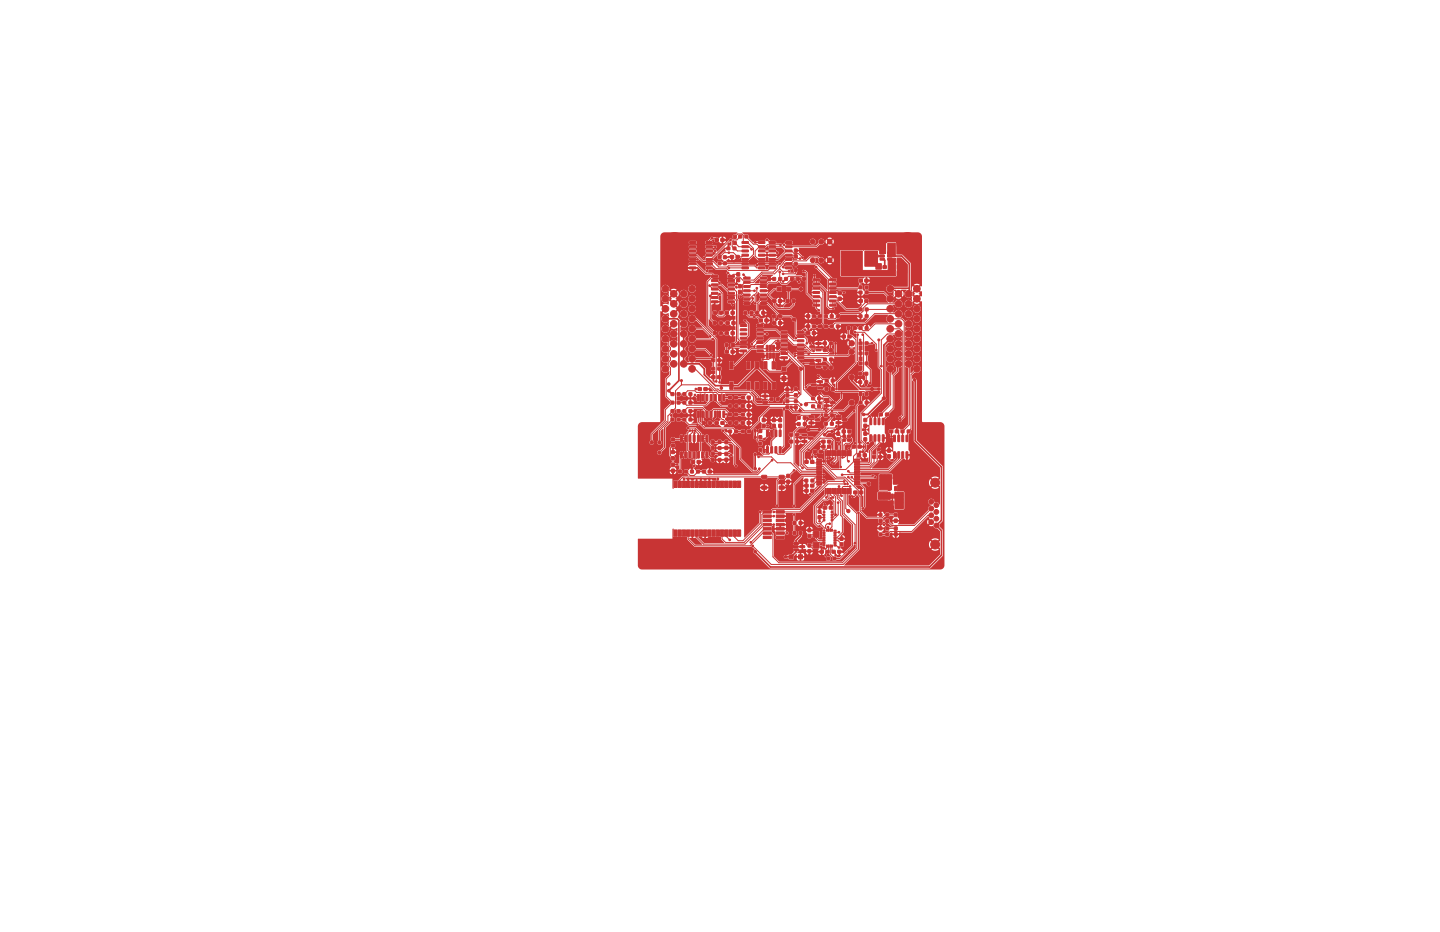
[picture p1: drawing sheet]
<svg xmlns="http://www.w3.org/2000/svg" width="432mm" height="279mm" viewBox="0 0 432 279" stroke-linecap="round" stroke-linejoin="round" font-family="sans-serif">
<g fill="#c83434" stroke="#c83434" stroke-width=".3">
<path d="M263.5 150.2h4.3v2.2h-4.3z"/>
<path d="M268.3 147.6h2.6v4.8h-2.6z"/>
<path d="M252.2 75.2h6.4v7.4h-6.4z"/>
<path d="M263.4 147.7h3.6v2h-3.6z"/>
<path d="M269.1 78h1.8v1l1 .6v2.2h-2.8z"/>
<path d="M262.5 70.9h3.1v5.1h-1.8v-1.3h-1.3z"/>
<path d="M252.3 81.1h16.3v1.5h-16.3z"/>
<path d="M267.8 143h3.6v2.1h-3.6z"/>
<path d="M266.2 72.9h2.3v4.1h-2.3z"/>
<path d="M263.8 142.3h3.5v4.6h-3.5z"/>
<path d="M259.3 75.2h3.8v1.3h1.9v.5h-1.9v2h1.2v1.7h-1.7v-.9h-3.3z"/>
<path d="M266.3 77.5h2.3v3.6h-2.3z"/>
<path d="M208.9 141h.8v.8h-.8z"/>
<path d="M207.1 141h.8v.8h-.8z"/>
<path d="M222 97.3h1.8l.1 .5-1.8 .1z"/>
<path d="M222 98.6h1.8l.1 .5h-1.8z"/>
<path d="M222 99.9l1.8-.1 .1 .5-1.8 .1z"/>
<path d="M222 101.1h1.8l.1 .5-1.8 .1z"/>
<path d="M222 102.4h1.8l.1 .5-1.8 .1z"/>
<path d="M222 103.7l1.8-.1 .1 .5-1.8 .1z"/>
<path d="M222 104.9h1.8l.1 .5-1.8 .1z"/>
<path d="M227 104.9h1.8l.1 .5-1.9 .1z"/>
<path d="M227 103.7l1.8-.1 .1 .5-1.9 .1z"/>
<path d="M227 102.4h1.8l.1 .5-1.9 .1z"/>
<path d="M227 101.1h1.8l.1 .5-1.9 .1z"/>
<path d="M227 99.9l1.8-.1 .1 .5-1.9 .1z"/>
<path d="M227 98.6h1.8l.1 .5h-1.9z"/>
<path d="M227 97.3h1.8l.1 .5-1.9 .1z"/>
<path d="M235.6 80.1l1.8-.1 .1 .5-1.8 .1z"/>
<path d="M235.6 78.8h1.8l.1 .4-1.8 .1z"/>
<path d="M235.6 77.5h1.8l.1 .5-1.8 .1z"/>
<path d="M235.6 76.2h1.8l.1 .5-1.8 .1z"/>
<path d="M235.6 75l1.8-.1 .1 .5-1.8 .1z"/>
<path d="M235.6 73.7h1.8l.1 .5-1.8 .1z"/>
<path d="M235.6 72.4h1.8l.1 .5-1.8 .1z"/>
<path d="M230.7 72.4h1.8v.5l-1.8 .1z"/>
<path d="M230.7 73.7h1.8v.5l-1.8 .1z"/>
<path d="M230.7 75l1.8-.1v.5l-1.8 .1z"/>
<path d="M230.7 76.2h1.8v.5l-1.8 .1z"/>
<path d="M230.7 77.5h1.8v.5l-1.8 .1z"/>
<path d="M230.7 78.8h1.8v.4l-1.8 .1z"/>
<path d="M230.7 80.1l1.8-.1v.5l-1.8 .1z"/>
<path d="M238.2 119.9h.8v.8h-.8z"/>
<path d="M238.2 121.7h.8v.8h-.8z"/>
<path d="M242.3 164.8h.8v.9h-.8z"/>
<path d="M242.3 163.1h.8v.9h-.8z"/>
<path d="M224.1 121.3h.9v.8h-.9z"/>
<path d="M222.3 121.3h.9v.8h-.9z"/>
<path d="M254.3 128.9h.9v.8h-.9z"/>
<path d="M252.5 128.9h1v.8h-1z"/>
<path d="M245.2 119h.9v.8h-.9z"/>
<path d="M243.4 119h.8v.8h-.8z"/>
<path d="M266.8 150.3h.9v.8h-.9z"/>
<path d="M268.5 150.3h.9v.8h-.9z"/>
<path d="M264.4 73.3h1v1.3h-1z"/>
<path d="M266.5 73.3h1v1.3h-1z"/>
<path d="M228.7 120.4l1.4-.1v.5l-1.3 .1z"/>
<path d="M228.7 118.5l1.4-.1v.5l-1.3 .1z"/>
<path d="M226.8 119.4h1.4l.1 .5-1.4 .1z"/>
<path d="M259.4 92.4h.9v.8h-.9z"/>
<path d="M257.6 92.4h.9v.8h-.9z"/>
<path d="M245.2 116.1l1.4-.1v.5l-1.3 .1z"/>
<path d="M245.2 114.2l1.4-.1v.5l-1.3 .1z"/>
<path d="M243.4 115.1h1.3l.1 .5-1.4 .1z"/>
<path d="M224.9 93.4h.8v.8h-.8z"/>
<path d="M223.1 93.4h.8v.8h-.8z"/>
<path d="M233.4 89.8h1v.8h-1z"/>
<path d="M231.7 89.8h.9v.8h-.9z"/>
<path d="M242.3 158.5h.8v.9h-.8z"/>
<path d="M242.3 160.2h.8v.9h-.8z"/>
<path d="M259.1 125.5h.8v.9h-.8z"/>
<path d="M259.1 127.2h.8v.9h-.8z"/>
<path d="M260.3 77.2h1.8v1.7h-1.8z"/>
<path d="M255.8 77.2h1.8v1.7h-1.8z"/>
<path d="M249 126.6h.9v.9h-.9z"/>
<path d="M247.2 126.6h.8v.9h-.8z"/>
<path d="M233.5 125.5h.8v.9h-.8z"/>
<path d="M233.5 127.2h.8v.9h-.8z"/>
<path d="M263.6 155.7h.8v.9h-.8z"/>
<path d="M263.6 153.9h.8v.8h-.8z"/>
<path d="M229.9 133.9l.5 .1-.1 1.8-.5-.1z"/>
<path d="M231.1 133.9l.6 .1-.1 1.8-.5-.1z"/>
<path d="M232.4 133.9l.6 .1-.1 1.8-.5-.1z"/>
<path d="M233.7 133.9l.5 .1-.1 1.8-.5-.1z"/>
<path d="M233.7 129h.5l-.1 1.9-.5-.1z"/>
<path d="M232.4 129h.6l-.1 1.9-.5-.1z"/>
<path d="M231.1 129h.6l-.1 1.9-.5-.1z"/>
<path d="M229.9 129h.5l-.1 1.9-.5-.1z"/>
<path d="M255 135.1l.2 .1v1.4h-.3z"/>
<path d="M254.5 135.1l.2 .1v1.4h-.3z"/>
<path d="M254 135.1l.2 .1v1.4h-.3z"/>
<path d="M253.5 135.1l.2 .1v1.4h-.3z"/>
<path d="M253 135.1l.2 .1v1.4h-.3z"/>
<path d="M252.5 135.1l.2 .1v1.4h-.3z"/>
<path d="M252 135.1l.2 .1v1.4h-.3z"/>
<path d="M251.5 135.1l.2 .1v1.4h-.3z"/>
<path d="M251 135.1l.2 .1v1.4h-.3z"/>
<path d="M250.5 135.1l.2 .1v1.4h-.3z"/>
<path d="M250 135.1l.2 .1v1.4h-.3z"/>
<path d="M249.5 135.1l.2 .1v1.4h-.3z"/>
<path d="M249 135.1l.2 .1v1.4h-.3z"/>
<path d="M248.5 135.1l.2 .1v1.4h-.3z"/>
<path d="M248 135.1l.2 .1v1.4h-.3z"/>
<path d="M247.5 135.1l.2 .1v1.4h-.3z"/>
<path d="M244.9 137.6h1.5v.3h-1.4z"/>
<path d="M244.9 138.1h1.5v.3h-1.4z"/>
<path d="M244.9 138.6h1.5v.3h-1.4z"/>
<path d="M244.9 139.1h1.5v.3h-1.4z"/>
<path d="M244.9 139.6h1.5v.3h-1.4z"/>
<path d="M244.9 140.1h1.5v.3h-1.4z"/>
<path d="M244.9 140.6h1.5v.3h-1.4z"/>
<path d="M244.9 141.1h1.5v.3h-1.4z"/>
<path d="M244.9 141.6h1.5v.3h-1.4z"/>
<path d="M244.9 142.1h1.5v.3h-1.4z"/>
<path d="M244.9 142.6h1.5v.3h-1.4z"/>
<path d="M244.9 143.1h1.5v.3h-1.4z"/>
<path d="M244.9 143.6h1.5v.3h-1.4z"/>
<path d="M244.9 144.1h1.5v.3h-1.4z"/>
<path d="M244.9 144.6h1.5v.3h-1.4z"/>
<path d="M244.9 145.1h1.5v.3h-1.4z"/>
<path d="M247.5 146.4l.2 .1v1.5l-.3-.1z"/>
<path d="M248 146.4l.2 .1v1.5l-.3-.1z"/>
<path d="M248.5 146.4l.2 .1v1.5l-.3-.1z"/>
<path d="M249 146.4l.2 .1v1.5l-.3-.1z"/>
<path d="M249.5 146.4l.2 .1v1.5l-.3-.1z"/>
<path d="M250 146.4l.2 .1v1.5l-.3-.1z"/>
<path d="M250.5 146.4l.2 .1v1.5l-.3-.1z"/>
<path d="M251 146.4l.2 .1v1.5l-.3-.1z"/>
<path d="M251.5 146.4l.2 .1v1.5l-.3-.1z"/>
<path d="M252 146.4l.2 .1v1.5l-.3-.1z"/>
<path d="M252.5 146.4l.2 .1v1.5l-.3-.1z"/>
<path d="M253 146.4l.2 .1v1.5l-.3-.1z"/>
<path d="M253.5 146.4l.2 .1v1.5l-.3-.1z"/>
<path d="M254 146.4l.2 .1v1.5l-.3-.1z"/>
<path d="M254.5 146.4l.2 .1v1.5l-.3-.1z"/>
<path d="M255 146.4l.2 .1v1.5l-.3-.1z"/>
<path d="M256.3 145.1h1.4l.1 .3h-1.5z"/>
<path d="M256.3 144.6h1.4l.1 .3h-1.5z"/>
<path d="M256.3 144.1h1.4l.1 .3h-1.5z"/>
<path d="M256.3 143.6h1.4l.1 .3h-1.5z"/>
<path d="M256.3 143.1h1.4l.1 .3h-1.5z"/>
<path d="M256.3 142.6h1.4l.1 .3h-1.5z"/>
<path d="M256.3 142.1h1.4l.1 .3h-1.5z"/>
<path d="M256.3 141.6h1.4l.1 .3h-1.5z"/>
<path d="M256.3 141.1h1.4l.1 .3h-1.5z"/>
<path d="M256.3 140.6h1.4l.1 .3h-1.5z"/>
<path d="M256.3 140.1h1.4l.1 .3h-1.5z"/>
<path d="M256.3 139.6h1.4l.1 .3h-1.5z"/>
<path d="M256.3 139.1h1.4l.1 .3h-1.5z"/>
<path d="M256.3 138.6h1.4l.1 .3h-1.5z"/>
<path d="M256.3 138.1h1.4l.1 .3h-1.5z"/>
<path d="M256.3 137.6h1.4l.1 .3h-1.5z"/>
<path d="M227.6 130.6h.8v.9h-.8z"/>
<path d="M227.6 128.8h.8v.8h-.8z"/>
<path d="M231.7 94.4h.8v.8h-.8z"/>
<path d="M233.5 94.4h.9v.8h-.9z"/>
<path d="M221.5 87.1h.8v.9h-.8z"/>
<path d="M221.5 85.3h.8v1h-.8z"/>
<path d="M243.4 121.4h.8v.8h-.8z"/>
<path d="M245.2 121.4h.9v.8h-.9z"/>
<path d="M247 109.9h.8v.8h-.8z"/>
<path d="M248.8 109.9h.8v.8h-.8z"/>
<path d="M215.4 135.6h.8v.9h-.8z"/>
<path d="M215.4 137.4h.8v.9h-.8z"/>
<path d="M221 81.8h.8v.9h-.8z"/>
<path d="M221 83.5h.8v.9h-.8z"/>
<path d="M238.2 118h.8v.9h-.8z"/>
<path d="M238.2 116.2h.8v.8h-.8z"/>
<path d="M265.5 123.8h.9v.9h-.9z"/>
<path d="M263.7 123.8h.9v.9h-.9z"/>
<path d="M250.8 97.4h.8v.8h-.8z"/>
<path d="M249 97.4h.8v.8h-.8z"/>
<path d="M249.2 153.3h.5v.4h-.5z"/>
<path d="M249.2 154.1h.5v.4h-.5z"/>
<path d="M249.2 154.9h.5v.4h-.5z"/>
<path d="M249.2 155.7h.5v.4h-.5z"/>
<path d="M246.9 155.7h.4v.4h-.4z"/>
<path d="M246.9 154.9h.4v.4h-.4z"/>
<path d="M246.9 154.1h.4v.4h-.4z"/>
<path d="M246.9 153.3h.4v.4h-.4z"/>
<path d="M231.6 125.5h.9v.9h-.9z"/>
<path d="M231.6 127.2h.9v.9h-.9z"/>
<path d="M214.4 71.5h1v.8h-1z"/>
<path d="M216.2 71.5h.9v.8h-.9z"/>
<path d="M256 147.2h1v.8h-1z"/>
<path d="M257.7 147.2h1v.8h-1z"/>
<path d="M242.6 124.6h1.3l.1 .5-1.4 .1z"/>
<path d="M242.6 126.5h1.3l.1 .5-1.4 .1z"/>
<path d="M244.5 125.6l1.3-.1 .1 .5-1.4 .1z"/>
<path d="M224.1 128.9h.9v.8h-.9z"/>
<path d="M222.3 128.9h.9v.8h-.9z"/>
<path d="M202 158.9h1v1.9h-1z"/>
<path d="M203.3 158.9h1v1.9h-1z"/>
<path d="M204.6 158.9h1v1.9h-1z"/>
<path d="M205.9 158.9h1v1.9h-1z"/>
<path d="M207.1 158.9h1v1.9h-1z"/>
<path d="M208.4 158.9h1v1.9h-1z"/>
<path d="M209.7 158.9h1v1.9h-1z"/>
<path d="M210.9 158.9h1v1.9h-1z"/>
<path d="M212.2 158.9h1v1.9h-1z"/>
<path d="M213.5 158.9h1v1.9h-1z"/>
<path d="M214.7 158.9h1v1.9h-1z"/>
<path d="M216 158.9h1v1.9h-1z"/>
<path d="M217.3 158.9h1v1.9h-1z"/>
<path d="M218.6 158.9h1v1.9h-1z"/>
<path d="M219.8 158.9h1v1.9h-1z"/>
<path d="M221.1 158.9h1v1.9h-1z"/>
<path d="M221.1 144.2h1v1.9h-1z"/>
<path d="M219.8 144.2h1v1.9h-1z"/>
<path d="M218.6 144.2h1v1.9h-1z"/>
<path d="M217.3 144.2h1v1.9h-1z"/>
<path d="M216 144.2h1v1.9h-1z"/>
<path d="M214.7 144.2h1v1.9h-1z"/>
<path d="M213.5 144.2h1v1.9h-1z"/>
<path d="M212.2 144.2h1v1.9h-1z"/>
<path d="M210.9 144.2h1v1.9h-1z"/>
<path d="M209.7 144.2h1v1.9h-1z"/>
<path d="M208.4 144.2h1v1.9h-1z"/>
<path d="M207.1 144.2h1v1.9h-1z"/>
<path d="M205.9 144.2h1v1.9h-1z"/>
<path d="M204.6 144.2h1v1.9h-1z"/>
<path d="M203.3 144.2h1v1.9h-1z"/>
<path d="M202 144.2h1v1.9h-1z"/>
<path d="M241.4 145.2h.9v.8h-.9z"/>
<path d="M243.1 145.2h.9v.8h-.9z"/>
<path d="M219.2 99.5h.9v.8h-.9z"/>
<path d="M217.5 99.5h.9v.8h-.9z"/>
<path d="M233.5 96.4h.9v.8h-.9z"/>
<path d="M231.7 96.4h.9v.8h-.9z"/>
<path d="M217 76.7h.8v.8h-.8z"/>
<path d="M217 78.5h.8v.9h-.8z"/>
<path d="M201.2 122.8h.9v.8h-.9z"/>
<path d="M203.1 122.8h.8v.8h-.8z"/>
<path d="M264.8 79.7h.9v.8h-.9z"/>
<path d="M263.1 79.7h.9v.8h-.9z"/>
<path d="M235.9 86.1h1.2v1.2h-1.2z"/>
<path d="M233.1 86.1h1.2v1.2h-1.2z"/>
<path d="M240.6 130.2l1.3-.1 .1 .5-1.4 .1z"/>
<path d="M240.6 132.1l1.3-.1 .1 .5-1.4 .1z"/>
<path d="M242.4 131.1h1.4l.1 .5-1.4 .1z"/>
<path d="M266.4 148.1l.5 .1-.1 1.2-.5-.1z"/>
<path d="M267.3 148.1l.6 .1-.1 1.2-.5-.1z"/>
<path d="M268.3 148.1l.5 .1-.1 1.2-.5-.1z"/>
<path d="M268.3 145.9h.5l-.1 1.2h-.5z"/>
<path d="M266.4 145.9h.5l-.1 1.2h-.5z"/>
<path d="M257.3 133.5h.9v.8h-.9z"/>
<path d="M255.6 133.5h.9v.8h-.9z"/>
<path d="M228.5 93.4h.8v.8h-.8z"/>
<path d="M226.6 93.4h.9v.8h-.9z"/>
<path d="M245.9 165h1v.8h-1z"/>
<path d="M247.7 165h.9v.8h-.9z"/>
<path d="M222.5 72.4h1.8l.1 .5-1.8 .1z"/>
<path d="M222.5 73.7h1.8l.1 .5-1.8 .1z"/>
<path d="M222.5 75l1.8-.1 .1 .5-1.8 .1z"/>
<path d="M222.5 76.2h1.8l.1 .5-1.8 .1z"/>
<path d="M222.5 77.5h1.8l.1 .5-1.8 .1z"/>
<path d="M222.5 78.8h1.8l.1 .4-1.8 .1z"/>
<path d="M222.5 80.1l1.8-.1 .1 .5-1.8 .1z"/>
<path d="M227.5 80.1l1.8-.1 .1 .5-1.9 .1z"/>
<path d="M227.5 78.8h1.8l.1 .4-1.9 .1z"/>
<path d="M227.5 77.5h1.8l.1 .5-1.9 .1z"/>
<path d="M227.5 76.2h1.8l.1 .5-1.9 .1z"/>
<path d="M227.5 75l1.8-.1 .1 .5-1.9 .1z"/>
<path d="M227.5 73.7h1.8l.1 .5-1.9 .1z"/>
<path d="M227.5 72.4h1.8l.1 .5-1.9 .1z"/>
<path d="M213.3 132.1h.8v.8h-.8z"/>
<path d="M213.3 133.9h.8v.8h-.8z"/>
<path d="M220.3 118.8h.9v.8h-.9z"/>
<path d="M218.5 118.8h.8v.8h-.8z"/>
<path d="M220.3 128.9h.9v.8h-.9z"/>
<path d="M218.5 128.9h.8v.8h-.8z"/>
<path d="M224.1 123.9h.9v.8h-.9z"/>
<path d="M222.3 123.9h.9v.8h-.9z"/>
<path d="M251.2 165h1v.8h-1z"/>
<path d="M249.5 165h.9v.8h-.9z"/>
<path d="M223.4 70.5h.8v.8h-.8z"/>
<path d="M221.6 70.5h.8v.8h-.8z"/>
<path d="M254.1 97.9h.8v.9h-.8z"/>
<path d="M255.9 97.9h.8v.9h-.8z"/>
<path d="M205.3 141h.9v.8h-.9z"/>
<path d="M203.5 141h.9v.8h-.9z"/>
<path d="M257.1 136h.9v.9h-.9z"/>
<path d="M258.8 136h1v.9h-1z"/>
<path d="M235.3 83.2h.8v.8h-.8z"/>
<path d="M237.1 83.2h.8v.8h-.8z"/>
<path d="M209.4 116.2h.9v.8h-.9z"/>
<path d="M211.1 116.2h.9v.8h-.9z"/>
<path d="M250.9 131.3h.8v.9h-.8z"/>
<path d="M250.9 129.5h.8v1h-.8z"/>
<path d="M220.3 121.3h.9v.8h-.9z"/>
<path d="M218.5 121.3h.8v.8h-.8z"/>
<path d="M239.6 159.4h.9v.8h-.9z"/>
<path d="M237.8 159.4h.8v.8h-.8z"/>
<path d="M209.2 123.3h.5l-.1 1.9-.5-.1z"/>
<path d="M210.4 123.3h.6l-.1 1.9-.5-.1z"/>
<path d="M211.7 123.3h.5v1.9l-.5-.1z"/>
<path d="M213 123.3h.5l-.1 1.9-.5-.1z"/>
<path d="M214.2 123.3h.6l-.1 1.9-.5-.1z"/>
<path d="M215.5 123.3h.6l-.1 1.9-.5-.1z"/>
<path d="M216.8 123.3h.5l-.1 1.9-.4-.1z"/>
<path d="M216.8 118.3l.5 .1-.1 1.8-.4-.1z"/>
<path d="M215.5 118.3l.6 .1-.1 1.8-.5-.1z"/>
<path d="M214.2 118.3l.6 .1-.1 1.8-.5-.1z"/>
<path d="M213 118.3l.5 .1-.1 1.8-.5-.1z"/>
<path d="M211.7 118.3l.5 .1v1.8l-.5-.1z"/>
<path d="M210.4 118.3l.6 .1-.1 1.8-.5-.1z"/>
<path d="M209.2 118.3l.5 .1-.1 1.8-.5-.1z"/>
<path d="M245.3 154.6h.8v1h-.8z"/>
<path d="M245.3 152.9h.8v.9h-.8z"/>
<path d="M243.9 162.7h1.7v1.6h-1.7z"/>
<path d="M243.9 159.4h1.7v1.6h-1.7z"/>
<path d="M217.5 103h.8v.8h-.8z"/>
<path d="M219.3 103h.8v.8h-.8z"/>
<path d="M215.8 99.5h.8v.8h-.8z"/>
<path d="M213.9 99.5h.9v.8h-.9z"/>
<path d="M266.2 77.4h1.2l.1 .5-1.3 .1z"/>
<path d="M266.2 76.5h1.2l.1 .5h-1.3z"/>
<path d="M266.2 75.5h1.2l.1 .5-1.3 .1z"/>
<path d="M263.9 75.5h1.2l.1 .5-1.2 .1z"/>
<path d="M263.9 76.5h1.2l.1 .5h-1.2z"/>
<path d="M263.9 77.4h1.2l.1 .5-1.2 .1z"/>
<path d="M233.5 83.2h.9v.8h-.9z"/>
<path d="M231.7 83.2h.8v.8h-.8z"/>
<path d="M229.8 105.9h.5v1.5l-.5-.1z"/>
<path d="M230.8 105.9h.5l-.1 1.5-.5-.1z"/>
<path d="M231.7 105.9h.5v1.5l-.5-.1z"/>
<path d="M231.7 103.6h.5v1.5l-.5-.1z"/>
<path d="M230.8 103.6h.5l-.1 1.5-.5-.1z"/>
<path d="M229.8 103.6h.5v1.5l-.5-.1z"/>
<path d="M257.5 114.2h.9v.8h-.9z"/>
<path d="M259.3 114.2h.9v.8h-.9z"/>
<path d="M245.4 94.4h.9v.8h-.9z"/>
<path d="M247.3 94.4h.8v.8h-.8z"/>
<path d="M252.8 131.6h.8v.7h-.8z"/>
<path d="M254.2 131.6h.8v.7h-.8z"/>
<path d="M254.2 130.5h.8v.7h-.8z"/>
<path d="M252.8 130.5h.8v.7h-.8z"/>
<path d="M234.2 99.4l1.8-.1 .1 .5-1.8 .1z"/>
<path d="M234.2 100.6h1.8l.1 .5-1.8 .1z"/>
<path d="M234.2 101.9h1.8l.1 .5h-1.8z"/>
<path d="M234.2 103.2l1.8-.1 .1 .5-1.8 .1z"/>
<path d="M234.2 104.4h1.8l.1 .5-1.8 .1z"/>
<path d="M234.2 105.7h1.8l.1 .5-1.8 .1z"/>
<path d="M234.2 107l1.8-.1 .1 .5-1.8 .1z"/>
<path d="M239.2 107l1.8-.1 .1 .5-1.9 .1z"/>
<path d="M239.2 105.7h1.8l.1 .5-1.9 .1z"/>
<path d="M239.2 104.4h1.8l.1 .5-1.9 .1z"/>
<path d="M239.2 103.2l1.8-.1 .1 .5-1.9 .1z"/>
<path d="M239.2 101.9h1.8l.1 .5h-1.9z"/>
<path d="M239.2 100.6h1.8l.1 .5-1.9 .1z"/>
<path d="M239.2 99.4l1.8-.1 .1 .5-1.9 .1z"/>
<path d="M215.4 78.5h.8v.9h-.8z"/>
<path d="M215.4 76.7h.8v.8h-.8z"/>
<path d="M238 162.7l1.4-.1v.5l-1.3 .1z"/>
<path d="M238 164.6l1.4-.1v.5l-1.3 .1z"/>
<path d="M239.9 163.6h1.3l.1 .5-1.4 .1z"/>
<path d="M244.7 104.6h1.4v.5l-1.3 .1z"/>
<path d="M244.7 102.7h1.4v.5l-1.3 .1z"/>
<path d="M242.8 103.7l1.4-.1 .1 .5-1.4 .1z"/>
<path d="M272 128.9h.9v.8h-.9z"/>
<path d="M270.2 128.9h.9v.8h-.9z"/>
<path d="M236.6 166.3h1.2v1.2h-1.2z"/>
<path d="M239.4 166.3h1.2v1.2h-1.2z"/>
<path d="M268 135.4l.5 .1-.1 1.8h-.5z"/>
<path d="M269.2 135.4l.6 .1-.1 1.8h-.5z"/>
<path d="M270.4 135.4l.6 .1-.1 1.8h-.5z"/>
<path d="M271.7 135.4l.5 .1v1.8h-.5z"/>
<path d="M271.7 130.5h.5v1.9l-.5-.1z"/>
<path d="M270.4 130.5h.6l-.1 1.9-.5-.1z"/>
<path d="M269.2 130.5h.6l-.1 1.9-.5-.1z"/>
<path d="M268 130.5h.5l-.1 1.9-.5-.1z"/>
<path d="M204.8 117.8h.8v.8h-.8z"/>
<path d="M206.6 117.8h.8v.8h-.8z"/>
<path d="M207.3 138.1h1v.8h-1z"/>
<path d="M209.1 138.1h.9v.8h-.9z"/>
<path d="M257.6 120.3h.9v.8h-.9z"/>
<path d="M259.4 120.3h.9v.8h-.9z"/>
<path d="M240.6 83.2h.9v.8h-.9z"/>
<path d="M238.8 83.2h.9v.8h-.9z"/>
<path d="M239.6 156.4h.9v.8h-.9z"/>
<path d="M237.8 156.4h.8v.8h-.8z"/>
<path d="M247 151.8h.9v.8h-.9z"/>
<path d="M248.7 151.8h.9v.8h-.9z"/>
<path d="M210.6 141h1v.8h-1z"/>
<path d="M212.4 141h.9v.8h-.9z"/>
<path d="M238.2 76.4h.8v.9h-.8z"/>
<path d="M238.2 74.7h.8v.9h-.8z"/>
<path d="M235.7 116.3h.8v.9h-.8z"/>
<path d="M235.7 118.1h.8v.9h-.8z"/>
<path d="M268 144.2h.9v.8h-.9z"/>
<path d="M266.3 144.2h.9v.8h-.9z"/>
<path d="M266.8 128.9h.9v.8h-.9z"/>
<path d="M268.5 128.9h.9v.8h-.9z"/>
<path d="M239.1 126.7h.8v.8h-.8z"/>
<path d="M240.9 126.7h.8v.8h-.8z"/>
<path d="M248 167h.8v.8h-.8z"/>
<path d="M249.8 167h.8v.8h-.8z"/>
<path d="M219.2 105.1h.9v.8h-.9z"/>
<path d="M217.5 105.1h.9v.8h-.9z"/>
<path d="M243.9 135h.9v.8h-.9z"/>
<path d="M245.7 135h.9v.8h-.9z"/>
<path d="M243.6 97.4h.9v.8h-.9z"/>
<path d="M241.9 97.4h.9v.8h-.9z"/>
<path d="M249.3 113.7h.8v.8h-.8z"/>
<path d="M247.5 113.7h.8v.8h-.8z"/>
<path d="M269.1 79.4h1.1v1.3h-1.1z"/>
<path d="M267.1 79.4h1v1.3h-1z"/>
<path d="M240.9 124.9h.8v.8h-.8z"/>
<path d="M239.1 124.9h.8v.8h-.8z"/>
<path d="M266.2 136.3h.8v1h-.8z"/>
<path d="M266.2 134.6h.8v.9h-.8z"/>
<path d="M217.4 135.6h.8v1h-.8z"/>
<path d="M217.4 137.3h.8v1h-.8z"/>
<path d="M248.8 107.3h.8v.8h-.8z"/>
<path d="M247 107.3h.8v.8h-.8z"/>
<path d="M201.2 120.3h.9v.8h-.9z"/>
<path d="M203.1 120.3h.8v.8h-.8z"/>
<path d="M248.2 133.5h.9v.8h-.9z"/>
<path d="M246.4 133.5h1v.8h-1z"/>
<path d="M223 83.1h1.8l.1 .5h-1.8z"/>
<path d="M223 84.4l1.8-.1 .1 .5-1.8 .1z"/>
<path d="M223 85.6h1.8l.1 .5-1.8 .1z"/>
<path d="M223 86.9h1.8l.1 .5-1.8 .1z"/>
<path d="M223 88.2h1.8l.1 .4-1.8 .1z"/>
<path d="M223 89.5l1.8-.1 .1 .5-1.8 .1z"/>
<path d="M223 90.7h1.8l.1 .5-1.8 .1z"/>
<path d="M228 90.7h1.8l.1 .5-1.9 .1z"/>
<path d="M228 89.5l1.8-.1 .1 .5-1.9 .1z"/>
<path d="M228 88.2h1.8l.1 .4-1.9 .1z"/>
<path d="M228 86.9h1.8l.1 .5-1.9 .1z"/>
<path d="M228 85.6h1.8l.1 .5-1.9 .1z"/>
<path d="M228 84.4l1.8-.1 .1 .5-1.9 .1z"/>
<path d="M228 83.1h1.8l.1 .5h-1.9z"/>
<path d="M261.7 136.5h.8v.9h-.8z"/>
<path d="M263.5 136.5h.8v.9h-.8z"/>
<path d="M244.7 109.7h1.4v.5l-1.3 .1z"/>
<path d="M244.7 107.8h1.4v.5l-1.3 .1z"/>
<path d="M242.8 108.8l1.4-.1 .1 .5-1.4 .1z"/>
<path d="M268.2 153.9h.8v.9h-.8z"/>
<path d="M268.2 155.6h.8v1h-.8z"/>
<path d="M257.6 105.5h.9v.8h-.9z"/>
<path d="M259.4 105.5h.9v.8h-.9z"/>
<path d="M213.4 110.1h.9v.8h-.9z"/>
<path d="M215.2 110.1h.9v.8h-.9z"/>
<path d="M248.2 132h.9v.8h-.9z"/>
<path d="M246.4 132h1v.8h-1z"/>
<path d="M247.2 119.5h1.3l.1 .5h-1.4z"/>
<path d="M247.2 121.4h1.3l.1 .5h-1.4z"/>
<path d="M249 120.4h1.4l.1 .5-1.4 .1z"/>
<path d="M248.8 91.2h1.8l.1 .5-1.8 .1z"/>
<path d="M248.8 90l1.8-.1 .1 .5-1.8 .1z"/>
<path d="M248.8 88.7h1.8l.1 .5h-1.8z"/>
<path d="M248.8 87.4h1.8l.1 .5-1.8 .1z"/>
<path d="M248.8 86.2l1.8-.1 .1 .5-1.8 .1z"/>
<path d="M248.8 84.9l1.8-.1 .1 .5-1.8 .1z"/>
<path d="M248.8 83.6h1.8l.1 .5-1.8 .1z"/>
<path d="M243.9 83.6h1.8l.1 .5-1.9 .1z"/>
<path d="M243.9 84.9l1.8-.1 .1 .5-1.9 .1z"/>
<path d="M243.9 86.2l1.8-.1 .1 .5-1.9 .1z"/>
<path d="M243.9 87.4h1.8l.1 .5-1.9 .1z"/>
<path d="M243.9 88.7h1.8l.1 .5h-1.9z"/>
<path d="M243.9 90l1.8-.1 .1 .5-1.9 .1z"/>
<path d="M243.9 91.2h1.8l.1 .5-1.9 .1z"/>
<path d="M228.6 127.2h.8v.9h-.8z"/>
<path d="M228.6 125.5h.8v.9h-.8z"/>
<path d="M218.8 114.5h1v2.2h-1z"/>
<path d="M223.9 114.5h1v2.2h-1z"/>
<path d="M226.4 114.5h1v2.2h-1z"/>
<path d="M229 114.5h1v2.2h-1z"/>
<path d="M231.5 114.5h1v2.2h-1z"/>
<path d="M231.5 108.4h1v2.2h-1z"/>
<path d="M229 108.4h1v2.2h-1z"/>
<path d="M226.4 108.4h1v2.2h-1z"/>
<path d="M223.9 108.4h1v2.2h-1z"/>
<path d="M218.8 108.4h1v2.2h-1z"/>
<path d="M204.8 122.8h.8v.8h-.8z"/>
<path d="M206.6 122.8h.8v.8h-.8z"/>
<path d="M216.2 126.4h.9v.8h-.9z"/>
<path d="M214.4 126.4h1v.8h-1z"/>
<path d="M259.4 85.7h.9v.9h-.9z"/>
<path d="M257.6 85.7h.9v.9h-.9z"/>
<path d="M243.2 143.7h.8v.8h-.8z"/>
<path d="M241.4 143.7h.8v.8h-.8z"/>
<path d="M265.7 158h.8v.8h-.8z"/>
<path d="M265.7 159.8h.8v.8h-.8z"/>
<path d="M215.8 93.4h.8v.8h-.8z"/>
<path d="M213.9 93.4h.9v.8h-.9z"/>
<path d="M247.5 116.2h.8v.8h-.8z"/>
<path d="M249.3 116.2h.8v.8h-.8z"/>
<path d="M257.6 94.4h.9v.8h-.9z"/>
<path d="M259.4 94.4h.9v.8h-.9z"/>
<path d="M219.5 96.4h.9v.8h-.9z"/>
<path d="M217.7 96.4h1v.8h-1z"/>
<path d="M263.6 159.8h.8v.8h-.8z"/>
<path d="M263.6 158h.8v.8h-.8z"/>
<path d="M206.8 72.4h1.8l.1 .5-1.9 .1z"/>
<path d="M206.8 73.7h1.8l.1 .5-1.9 .1z"/>
<path d="M206.8 75l1.8-.1 .1 .5-1.9 .1z"/>
<path d="M206.8 76.2h1.8l.1 .5-1.9 .1z"/>
<path d="M206.8 77.5h1.8l.1 .5-1.9 .1z"/>
<path d="M206.8 78.8h1.8l.1 .4-1.9 .1z"/>
<path d="M206.8 80.1l1.8-.1 .1 .5-1.9 .1z"/>
<path d="M211.7 80.1l1.8-.1 .1 .5-1.8 .1z"/>
<path d="M211.7 78.8h1.8l.1 .4-1.8 .1z"/>
<path d="M211.7 77.5h1.8l.1 .5-1.8 .1z"/>
<path d="M211.7 76.2h1.8l.1 .5-1.8 .1z"/>
<path d="M211.7 75l1.8-.1 .1 .5-1.8 .1z"/>
<path d="M211.7 73.7h1.8l.1 .5-1.8 .1z"/>
<path d="M211.7 72.4h1.8l.1 .5-1.8 .1z"/>
<path d="M215.4 132.1h.8v.8h-.8z"/>
<path d="M215.4 133.9h.8v.8h-.8z"/>
<path d="M220.3 123.8h.9v.8h-.9z"/>
<path d="M218.5 123.8h.8v.8h-.8z"/>
<path d="M250.7 124.6l1.4-.1v.5l-1.3 .1z"/>
<path d="M250.7 126.5l1.4-.1v.5l-1.3 .1z"/>
<path d="M252.6 125.5h1.3l.1 .5-1.4 .1z"/>
<path d="M217.4 132.1h.8v.9h-.8z"/>
<path d="M217.4 133.8h.8v.9h-.8z"/>
<path d="M227.6 95.7h1v.8h-1z"/>
<path d="M229.4 95.7h.9v.8h-.9z"/>
<path d="M249 94.4h.8v.8h-.8z"/>
<path d="M250.8 94.4h.8v.8h-.8z"/>
<path d="M238.6 132h.9v.8h-.9z"/>
<path d="M236.8 132h.8v.8h-.8z"/>
<path d="M268.2 158h.8v.9h-.8z"/>
<path d="M268.2 159.7h.8v.9h-.8z"/>
<path d="M220.7 76.6h1v.8h-1z"/>
<path d="M219 76.6h.9v.8h-.9z"/>
<path d="M201.2 125.4h.9v.8h-.9z"/>
<path d="M203.1 125.4h.8v.8h-.8z"/>
<path d="M232.8 160.7h2.4v.8h-2.4z"/>
<path d="M228.9 160.7h2.4v.8h-2.4z"/>
<path d="M232.8 159.4h2.4v.8h-2.4z"/>
<path d="M228.9 159.4h2.4v.8h-2.4z"/>
<path d="M232.8 158.2h2.4v.7h-2.4z"/>
<path d="M228.9 158.2h2.4v.7h-2.4z"/>
<path d="M232.8 156.9h2.4v.7h-2.4z"/>
<path d="M228.9 156.9h2.4v.7h-2.4z"/>
<path d="M232.8 155.6h2.4v.8h-2.4z"/>
<path d="M228.9 155.6h2.4v.8h-2.4z"/>
<path d="M232.8 154.4h2.4v.7h-2.4z"/>
<path d="M228.9 154.4h2.4v.7h-2.4z"/>
<path d="M232.8 153.1h2.4v.7h-2.4z"/>
<path d="M228.9 153.1h2.4v.7h-2.4z"/>
<path d="M259.4 117.7h.9v.8h-.9z"/>
<path d="M257.6 117.7h.9v.8h-.9z"/>
<path d="M259.4 102.5h.9v.8h-.9z"/>
<path d="M257.6 102.5h.9v.8h-.9z"/>
<path d="M243.1 138.1h.9v.8h-.9z"/>
<path d="M241.4 138.1h.9v.8h-.9z"/>
<path d="M260.9 130.4h.5l-.1 1.9-.5-.1z"/>
<path d="M262.1 130.4h.6l-.1 1.9-.5-.1z"/>
<path d="M263.3 130.4h.6l-.1 1.9-.5-.1z"/>
<path d="M264.6 130.4h.5l-.1 1.9-.4-.1z"/>
<path d="M264.6 125.4l.5 .1-.1 1.8-.4-.1z"/>
<path d="M263.3 125.4l.6 .1-.1 1.8-.5-.1z"/>
<path d="M262.1 125.4l.6 .1-.1 1.8-.5-.1z"/>
<path d="M260.9 125.4l.5 .1-.1 1.8-.5-.1z"/>
<path d="M257.5 111.6h.9v.8h-.9z"/>
<path d="M259.3 111.6h.9v.8h-.9z"/>
<path d="M241.9 99.5h.9v.8h-.9z"/>
<path d="M243.6 99.5h.9v.8h-.9z"/>
<path d="M235.9 144h.9v.9h-.9z"/>
<path d="M235.9 142.2h.9v1h-.9z"/>
<path d="M201.4 138.9h.8v1h-.8z"/>
<path d="M201.4 140.7h.8v.9h-.8z"/>
<path d="M243.1 146.7h.9v.8h-.9z"/>
<path d="M241.4 146.7h.9v.8h-.9z"/>
<path d="M201.2 117.8h.9v.8h-.9z"/>
<path d="M203.1 117.8h.8v.8h-.8z"/>
<path d="M213.3 135.6h.8v.9h-.8z"/>
<path d="M213.3 137.4h.8v.9h-.8z"/>
<path d="M231 119.3h.8v.8h-.8z"/>
<path d="M232.8 119.3h.8v.8h-.8z"/>
<path d="M204.8 125.4h.8v.8h-.8z"/>
<path d="M206.6 125.4h.8v.8h-.8z"/>
<path d="M259.3 89.8h1v.8h-1z"/>
<path d="M257.6 89.8h1v.8h-1z"/>
<path d="M204.8 120.3h.8v.8h-.8z"/>
<path d="M206.6 120.3h.8v.8h-.8z"/>
<path d="M237.6 89.8h.8v.8h-.8z"/>
<path d="M235.8 89.8h.8v.8h-.8z"/>
<path d="M251.4 87.4h.8v.9h-.8z"/>
<path d="M251.4 89.1h.8v.9h-.8z"/>
<path d="M215.8 96.4h.8v.8h-.8z"/>
<path d="M213.9 96.4h.9v.8h-.9z"/>
<path d="M213.4 82.6h1.8l.1 .5h-1.9z"/>
<path d="M213.4 83.9l1.8-.1 .1 .5-1.9 .1z"/>
<path d="M213.4 85.1h1.8l.1 .5-1.9 .1z"/>
<path d="M213.4 86.4h1.8l.1 .5-1.9 .1z"/>
<path d="M213.4 87.7l1.8-.1 .1 .5-1.9 .1z"/>
<path d="M213.4 88.9h1.8l.1 .5-1.9 .1z"/>
<path d="M213.4 90.2h1.8l.1 .5-1.9 .1z"/>
<path d="M218.3 90.2h1.8l.1 .5-1.8 .1z"/>
<path d="M218.3 88.9h1.8l.1 .5-1.8 .1z"/>
<path d="M218.3 87.7l1.8-.1 .1 .5-1.8 .1z"/>
<path d="M218.3 86.4h1.8l.1 .5-1.8 .1z"/>
<path d="M218.3 85.1h1.8l.1 .5-1.8 .1z"/>
<path d="M218.3 83.9l1.8-.1 .1 .5-1.8 .1z"/>
<path d="M218.3 82.6h1.8l.1 .5h-1.8z"/>
<path d="M204.1 135.4l.5 .1-.1 1.8h-.4z"/>
<path d="M205.4 135.4l.5 .1-.1 1.8h-.5z"/>
<path d="M206.6 135.4l.6 .1-.1 1.8h-.5z"/>
<path d="M207.9 135.4l.5 .1v1.8h-.5z"/>
<path d="M209.2 135.4l.5 .1-.1 1.8h-.5z"/>
<path d="M210.4 135.4l.6 .1-.1 1.8h-.5z"/>
<path d="M211.7 135.4l.5 .1v1.8h-.5z"/>
<path d="M211.7 130.5h.5v1.9l-.5-.1z"/>
<path d="M210.4 130.5h.6l-.1 1.9-.5-.1z"/>
<path d="M209.2 130.5h.5l-.1 1.9-.5-.1z"/>
<path d="M207.9 130.5h.5v1.9l-.5-.1z"/>
<path d="M206.6 130.5h.6l-.1 1.9-.5-.1z"/>
<path d="M205.4 130.5h.5l-.1 1.9-.5-.1z"/>
<path d="M204.1 130.5h.5l-.1 1.9-.4-.1z"/>
<path d="M257.6 83.7h1v.8h-1z"/>
<path d="M259.3 83.7h1v.8h-1z"/>
<path d="M246.7 163.4h.7v.3h-.7z"/>
<path d="M247.8 163.4h.3v.6h-.3z"/>
<path d="M248.3 163.4h.3v.6h-.3z"/>
<path d="M248.8 163.4h.3v.6h-.3z"/>
<path d="M249.3 163.4h.3v.6h-.3z"/>
<path d="M250 163.4h.7v.3h-.7z"/>
<path d="M250 162.9h.7v.3h-.7z"/>
<path d="M250 162.4h.7v.3h-.7z"/>
<path d="M250 161.9h.7v.3h-.7z"/>
<path d="M250 161.4h.7v.3h-.7z"/>
<path d="M250 160.9h.7v.3h-.7z"/>
<path d="M250 160.4h.7v.3h-.7z"/>
<path d="M250 159.9h.7v.3h-.7z"/>
<path d="M250 159.4h.7v.3h-.7z"/>
<path d="M250 158.9h.7v.3h-.7z"/>
<path d="M249.3 158.6h.3v.7h-.3z"/>
<path d="M248.8 158.6h.3v.7h-.3z"/>
<path d="M248.3 158.6h.3v.7h-.3z"/>
<path d="M247.8 158.6h.3v.7h-.3z"/>
<path d="M246.7 158.9h.7v.3h-.7z"/>
<path d="M246.7 159.4h.7v.3h-.7z"/>
<path d="M246.7 159.9h.7v.3h-.7z"/>
<path d="M246.7 160.4h.7v.3h-.7z"/>
<path d="M246.7 160.9h.7v.3h-.7z"/>
<path d="M246.7 161.4h.7v.3h-.7z"/>
<path d="M246.7 161.9h.7v.3h-.7z"/>
<path d="M246.7 162.4h.7v.3h-.7z"/>
<path d="M246.7 162.9h.7v.3h-.7z"/>
<path d="M201.4 131.3h.8v.8h-.8z"/>
<path d="M201.4 133.1h.8v.9h-.8z"/>
<path d="M265.7 153.9h.8v.8h-.8z"/>
<path d="M265.7 155.7h.8v.9h-.8z"/>
<path d="M235.7 121.7h.8v.8h-.8z"/>
<path d="M235.7 119.9h.8v.8h-.8z"/>
<path d="M234.5 110.1h1.2v1.2h-1.2z"/>
<path d="M234.5 112.9h1.2v1.2h-1.2z"/>
<path d="M238.6 129.9h.9v.9h-.9z"/>
<path d="M236.8 129.9h.8v.9h-.8z"/>
<path d="M259.1 131.3h.8v.9h-.8z"/>
<path d="M259.1 129.5h.8v1h-.8z"/>
<path d="M219.2 93.4h.9v.8h-.9z"/>
<path d="M217.5 93.4h.9v.8h-.9z"/>
<path d="M201.4 135.1h.8v.9h-.8z"/>
<path d="M201.4 136.9h.8v.9h-.8z"/>
<path d="M224.1 118.8h.9v.8h-.9z"/>
<path d="M222.3 118.8h.9v.8h-.9z"/>
<path d="M227.6 134.4h.8v.8h-.8z"/>
<path d="M227.6 132.6h.8v.8h-.8z"/>
<path d="M251.9 161h.9v1h-.9z"/>
<path d="M251.9 162.7h.9v1h-.9z"/>
<path d="M220.3 126.4h.9v.8h-.9z"/>
<path d="M218.5 126.4h.8v.8h-.8z"/>
<path d="M243.6 94.4h.9v.8h-.9z"/>
<path d="M241.9 94.4h.9v.8h-.9z"/>
<path d="M249 124.1h.9v.8h-.9z"/>
<path d="M247.2 124.1h.8v.8h-.8z"/>
<path d="M213.4 107.6h.9v.8h-.9z"/>
<path d="M215.2 107.6h.9v.8h-.9z"/>
<path d="M247 104.5h.8v.9h-.8z"/>
<path d="M248.8 104.5h.8v.9h-.8z"/>
<path d="M257.6 87.3h.9v.8h-.9z"/>
<path d="M259.4 87.3h.9v.8h-.9z"/>
<path d="M247 102.5h.8v.8h-.8z"/>
<path d="M248.8 102.5h.8v.8h-.8z"/>
<path d="M218 74.1h.8v.8h-.8z"/>
<path d="M219.8 74.1h.9v.8h-.9z"/>
<path d="M257.6 97.9h.9v.9h-.9z"/>
<path d="M259.4 97.9h.9v.9h-.9z"/>
<path d="M219.9 72.4h.8v.9h-.8z"/>
<path d="M219.9 70.6h.8v.8h-.8z"/>
<path d="M247.3 97.4h.8v.8h-.8z"/>
<path d="M245.4 97.4h.9v.8h-.9z"/>
<path d="M233.7 145.7h1.3l.2 .8-1.4 .2z"/>
<path d="M228.4 145.7h1.4l.1 .8-1.4 .2z"/>
<path d="M233.7 142.5h1.3l.2 .8-1.4 .2z"/>
<path d="M228.4 142.5h1.4l.1 .8-1.4 .2z"/>
<path d="M212.5 126.4h.8v.8h-.8z"/>
<path d="M210.6 126.4h.9v.8h-.9z"/>
<path d="M224.1 126.4h.9v.8h-.9z"/>
<path d="M222.3 126.4h.9v.8h-.9z"/>
<path d="M238.2 78.7h.8v.9h-.8z"/>
<path d="M238.2 80.6h.8v.8h-.8z"/>
<path d="M215.1 112.7h1v.8h-1z"/>
<path d="M213.4 112.7h1v.8h-1z"/>
<path d="M257.6 108.5h.9v.9h-.9z"/>
<path d="M259.4 108.5h.9v.9h-.9z"/>
<path d="M254.3 100.5h.9v.8h-.9z"/>
<path d="M252.5 100.5h1v.8h-1z"/>
<circle cx="255.4" cy="102.9" r=".8"/>
<circle cx="255.4" cy="105.5" r=".8"/>
<circle cx="255.4" cy="113.1" r=".8"/>
<circle cx="255.4" cy="120.7" r=".8"/>
<circle cx="260.5" cy="145.1" r=".5"/>
<circle cx="240.2" cy="86.7" r=".5"/>
<circle cx="202.3" cy="72.9" r="3.2"/>
<circle cx="254.4" cy="153.2" r=".5"/>
<circle cx="278.5" cy="130.1" r="3.2"/>
<circle cx="196" cy="165.7" r="3.2"/>
<circle cx="263.5" cy="134.7" r=".5"/>
<circle cx="207.5" cy="86.6" r="1"/>
<circle cx="207.5" cy="89.6" r="1"/>
<circle cx="207.5" cy="92.6" r="1"/>
<circle cx="207.5" cy="95.6" r="1"/>
<circle cx="207.5" cy="98.6" r="1"/>
<circle cx="207.5" cy="101.6" r="1"/>
<circle cx="207.5" cy="104.6" r="1"/>
<circle cx="207.5" cy="107.6" r="1"/>
<circle cx="207.5" cy="110.6" r="1"/>
<circle cx="205" cy="88.1" r="1"/>
<circle cx="205" cy="91.1" r="1"/>
<circle cx="205" cy="94.1" r="1"/>
<circle cx="205" cy="97.1" r="1"/>
<circle cx="205" cy="100.1" r="1"/>
<circle cx="205" cy="103.1" r="1"/>
<circle cx="205" cy="106.1" r="1"/>
<circle cx="205" cy="109.1" r="1"/>
<circle cx="202" cy="88.1" r="1"/>
<circle cx="202" cy="91.1" r="1"/>
<circle cx="202" cy="94.1" r="1"/>
<circle cx="202" cy="97.1" r="1"/>
<circle cx="202" cy="100.1" r="1"/>
<circle cx="202" cy="103.1" r="1"/>
<circle cx="202" cy="106.1" r="1"/>
<circle cx="202" cy="109.1" r="1"/>
<circle cx="199.5" cy="86.6" r="1"/>
<circle cx="199.5" cy="89.6" r="1"/>
<circle cx="199.5" cy="92.6" r="1"/>
<circle cx="199.5" cy="95.6" r="1"/>
<circle cx="199.5" cy="98.6" r="1"/>
<circle cx="199.5" cy="101.6" r="1"/>
<circle cx="199.5" cy="104.6" r="1"/>
<circle cx="199.5" cy="107.6" r="1"/>
<circle cx="199.5" cy="110.6" r="1"/>
<circle cx="243.7" cy="78" r=".72"/>
<circle cx="246.3" cy="78" r=".72"/>
<circle cx="248.8" cy="78" r=".72"/>
<circle cx="261.5" cy="116.6" r=".5"/>
<circle cx="195.5" cy="132.6" r=".5"/>
<circle cx="241.7" cy="121.2" r=".5"/>
<circle cx="240.2" cy="110.5" r=".5"/>
<circle cx="265" cy="119.4" r=".5"/>
<circle cx="266.9" cy="110.6" r="1"/>
<circle cx="266.9" cy="107.6" r="1"/>
<circle cx="266.9" cy="104.6" r="1"/>
<circle cx="266.9" cy="101.6" r="1"/>
<circle cx="266.9" cy="98.6" r="1"/>
<circle cx="266.9" cy="95.6" r="1"/>
<circle cx="266.9" cy="92.6" r="1"/>
<circle cx="266.9" cy="89.6" r="1"/>
<circle cx="266.9" cy="86.6" r="1"/>
<circle cx="269.4" cy="109.1" r="1"/>
<circle cx="269.4" cy="106.1" r="1"/>
<circle cx="269.4" cy="103.1" r="1"/>
<circle cx="269.4" cy="100.1" r="1"/>
<circle cx="269.4" cy="97.1" r="1"/>
<circle cx="269.4" cy="94.1" r="1"/>
<circle cx="269.4" cy="91.1" r="1"/>
<circle cx="269.4" cy="88.1" r="1"/>
<circle cx="272.4" cy="109.1" r="1"/>
<circle cx="272.4" cy="106.1" r="1"/>
<circle cx="272.4" cy="103.1" r="1"/>
<circle cx="272.4" cy="100.1" r="1"/>
<circle cx="272.4" cy="97.1" r="1"/>
<circle cx="272.4" cy="94.1" r="1"/>
<circle cx="272.4" cy="91.1" r="1"/>
<circle cx="272.4" cy="88.1" r="1"/>
<circle cx="274.9" cy="110.6" r="1"/>
<circle cx="274.9" cy="107.6" r="1"/>
<circle cx="274.9" cy="104.6" r="1"/>
<circle cx="274.9" cy="101.6" r="1"/>
<circle cx="274.9" cy="98.6" r="1"/>
<circle cx="274.9" cy="95.6" r="1"/>
<circle cx="274.9" cy="92.6" r="1"/>
<circle cx="274.9" cy="89.6" r="1"/>
<circle cx="274.9" cy="86.6" r="1"/>
<circle cx="272.2" cy="72.9" r="3.2"/>
<circle cx="197.7" cy="132.6" r=".5"/>
<circle cx="243.7" cy="72.4" r=".72"/>
<circle cx="246.3" cy="72.4" r=".72"/>
<circle cx="248.8" cy="72.4" r=".72"/>
<circle cx="238.1" cy="95.8" r=".5"/>
<circle cx="280.8" cy="151.4" r=".72"/>
<circle cx="279.2" cy="150.4" r=".72"/>
<circle cx="279.2" cy="152.4" r=".72"/>
<circle cx="279.2" cy="154.5" r=".72"/>
<circle cx="280.8" cy="153.5" r=".72"/>
<circle cx="280.8" cy="155.5" r=".72"/>
<circle cx="280.8" cy="157.5" r=".72"/>
<circle cx="279.2" cy="156.5" r=".72"/>
<circle cx="280.4" cy="163.2" r="1.35"/>
<circle cx="280.4" cy="144.7" r="1.35"/>
<circle cx="197.7" cy="135.7" r=".5"/>
<circle cx="232" cy="158.5" r=".25"/>
<circle cx="264.8" cy="135.4" r=".25"/>
<circle cx="229.2" cy="135.4" r=".25"/>
<circle cx="219.1" cy="134.2" r=".25"/>
<circle cx="257.9" cy="88.9" r=".25"/>
<circle cx="218.6" cy="73.3" r=".25"/>
<circle cx="233.8" cy="88.9" r=".25"/>
<circle cx="220.1" cy="78.3" r=".25"/>
<circle cx="263" cy="74.5" r=".38"/>
<circle cx="214.2" cy="141.5" r=".25"/>
<circle cx="253.6" cy="161.6" r=".25"/>
<circle cx="251.6" cy="100.6" r=".25"/>
<circle cx="214.5" cy="77.8" r=".25"/>
<circle cx="264" cy="72.4" r=".38"/>
<circle cx="263" cy="71.4" r=".38"/>
<circle cx="217.8" cy="129.1" r=".25"/>
<circle cx="243.2" cy="98.9" r=".25"/>
<circle cx="263" cy="73.5" r=".38"/>
<circle cx="261" cy="84.1" r=".25"/>
<circle cx="207.4" cy="140.3" r=".25"/>
<circle cx="240.7" cy="145.6" r=".25"/>
<circle cx="217.8" cy="125.5" r=".25"/>
<circle cx="251.6" cy="128.3" r=".25"/>
<circle cx="229.2" cy="94.8" r=".25"/>
<circle cx="264.8" cy="151.9" r=".38"/>
<circle cx="264" cy="71.4" r=".38"/>
<circle cx="224.4" cy="125.5" r=".25"/>
<circle cx="252.3" cy="97.8" r=".25"/>
<circle cx="270.6" cy="81.6" r=".38"/>
<circle cx="271.4" cy="79.8" r=".38"/>
<circle cx="224.4" cy="120.4" r=".25"/>
<circle cx="265" cy="71.4" r=".38"/>
<circle cx="269.4" cy="128.1" r=".25"/>
<circle cx="265.8" cy="151.9" r=".38"/>
<circle cx="247" cy="144.6" r=".25"/>
<circle cx="254.1" cy="133.7" r=".25"/>
<circle cx="245.7" cy="152.2" r=".25"/>
<circle cx="269.9" cy="156.3" r=".25"/>
<circle cx="269.6" cy="81.6" r=".38"/>
<circle cx="265" cy="72.4" r=".38"/>
<circle cx="259.1" cy="119.4" r=".3"/>
<circle cx="242.9" cy="87.7" r=".3"/>
<circle cx="265" cy="133.1" r=".25"/>
<circle cx="257.9" cy="113.3" r=".25"/>
<circle cx="208.2" cy="133.1" r=".25"/>
<circle cx="214" cy="91.5" r=".25"/>
<circle cx="231" cy="83.6" r=".25"/>
<circle cx="227.5" cy="146.1" r=".25"/>
<circle cx="270.9" cy="144.6" r=".38"/>
<circle cx="213" cy="111.8" r=".25"/>
<circle cx="246" cy="109" r=".25"/>
<circle cx="219.1" cy="137.7" r=".25"/>
<circle cx="271.4" cy="80.8" r=".38"/>
<circle cx="206.4" cy="143.6" r=".25"/>
<circle cx="216.8" cy="108.5" r=".25"/>
<circle cx="270.6" cy="78.5" r=".38"/>
<circle cx="235.1" cy="114.9" r=".25"/>
<circle cx="246.3" cy="161.3" r=".25"/>
<circle cx="273.2" cy="136.7" r=".25"/>
<circle cx="245.7" cy="120.7" r=".25"/>
<circle cx="207.1" cy="124.5" r=".25"/>
<circle cx="257.9" cy="96.1" r=".25"/>
<circle cx="260" cy="97.3" r=".25"/>
<circle cx="254.6" cy="165.4" r=".25"/>
<circle cx="247" cy="164.4" r=".25"/>
<circle cx="242.7" cy="166.4" r=".25"/>
<circle cx="231" cy="118.4" r=".25"/>
<circle cx="207.6" cy="161.6" r=".25"/>
<circle cx="249.3" cy="151.2" r=".25"/>
<circle cx="269.6" cy="78.5" r=".38"/>
<circle cx="206.1" cy="80.3" r=".25"/>
<circle cx="235.3" cy="96.8" r=".25"/>
<circle cx="236.1" cy="154.7" r=".25"/>
<circle cx="233" cy="124.8" r=".25"/>
<circle cx="250.1" cy="108.3" r=".25"/>
<circle cx="224.4" cy="123" r=".25"/>
<circle cx="253.1" cy="89.7" r=".25"/>
<circle cx="233" cy="104.2" r=".25"/>
<circle cx="210.2" cy="143.6" r=".25"/>
<circle cx="270.9" cy="143.3" r=".38"/>
<circle cx="267.3" cy="124.3" r=".25"/>
<circle cx="252.9" cy="165.4" r=".25"/>
<circle cx="221.1" cy="105.2" r=".25"/>
<circle cx="269.9" cy="144.6" r=".38"/>
<circle cx="233.3" cy="107.2" r=".25"/>
<circle cx="213" cy="116.9" r=".25"/>
<circle cx="269.9" cy="143.3" r=".38"/>
<circle cx="246.5" cy="115.4" r=".25"/>
<circle cx="254.9" cy="148.9" r=".25"/>
<circle cx="239.9" cy="123.2" r=".25"/>
<circle cx="219.8" cy="95.3" r=".25"/>
<circle cx="240.2" cy="131.4" r=".25"/>
<circle cx="211.5" cy="161.6" r=".25"/>
<circle cx="250.8" cy="113.6" r=".25"/>
<circle cx="250.1" cy="125.8" r=".25"/>
<circle cx="242.7" cy="127.8" r=".25"/>
<circle cx="265.8" cy="150.9" r=".38"/>
<circle cx="262.8" cy="158.3" r=".25"/>
<circle cx="246" cy="101.9" r=".25"/>
<circle cx="245.7" cy="133.1" r=".25"/>
<circle cx="217.8" cy="127.6" r=".25"/>
<circle cx="257.9" cy="104.9" r=".25"/>
<circle cx="203.1" cy="135.7" r=".25"/>
<circle cx="229" cy="107" r=".25"/>
<circle cx="220.9" cy="85.1" r=".25"/>
<circle cx="242.2" cy="96.3" r=".25"/>
<circle cx="230" cy="76.5" r=".25"/>
<circle cx="263" cy="72.4" r=".38"/>
<circle cx="269.9" cy="160.1" r=".25"/>
<circle cx="229.7" cy="124.8" r=".25"/>
<circle cx="208.2" cy="119.4" r=".25"/>
<circle cx="247" cy="138.2" r=".25"/>
<circle cx="266.8" cy="151.9" r=".38"/>
<circle cx="230.5" cy="86.4" r=".25"/>
<circle cx="248.1" cy="138.3" r=".25"/>
<circle cx="240.2" cy="75.2" r=".25"/>
<circle cx="248.5" cy="93.6" r=".25"/>
<circle cx="247.3" cy="122.5" r=".25"/>
<circle cx="264.8" cy="150.9" r=".38"/>
<circle cx="219.8" cy="98.3" r=".25"/>
<circle cx="212.7" cy="143.6" r=".25"/>
<circle cx="241.7" cy="157.5" r=".25"/>
<circle cx="262.3" cy="124.5" r=".25"/>
<circle cx="253.1" cy="128.3" r=".25"/>
<circle cx="268.9" cy="143.3" r=".38"/>
<circle cx="259" cy="128.8" r=".3"/>
<circle cx="264" cy="153.2" r=".25"/>
<circle cx="201.8" cy="142.3" r=".25"/>
<circle cx="259.5" cy="137.7" r=".25"/>
<circle cx="209.4" cy="140" r=".25"/>
<circle cx="235.8" cy="145.6" r=".25"/>
<circle cx="238.4" cy="127.3" r=".25"/>
<circle cx="258.2" cy="146.4" r=".25"/>
<circle cx="241.2" cy="165.1" r=".38"/>
<circle cx="217.8" cy="71.9" r=".25"/>
<circle cx="259" cy="133.9" r=".25"/>
<circle cx="256.3" cy="132.9" r=".25"/>
<circle cx="247.5" cy="166.4" r=".25"/>
<circle cx="257.9" cy="135.4" r=".25"/>
<circle cx="243.6" cy="137" r=".25"/>
<circle cx="265.3" cy="143.8" r=".38"/>
<circle cx="267.6" cy="138" r=".25"/>
<circle cx="242.9" cy="148.1" r=".25"/>
<circle cx="264.3" cy="144.8" r=".38"/>
<circle cx="260.2" cy="132.9" r=".25"/>
<circle cx="236.1" cy="159.8" r=".25"/>
<circle cx="265.3" cy="144.8" r=".38"/>
<circle cx="246.3" cy="163.1" r=".25"/>
<circle cx="255.6" cy="148.9" r=".25"/>
<circle cx="247.3" cy="151.2" r=".25"/>
<circle cx="264.3" cy="145.8" r=".38"/>
<circle cx="265.3" cy="142.8" r=".38"/>
<circle cx="250.6" cy="166.4" r=".25"/>
<circle cx="264.3" cy="142.8" r=".38"/>
<circle cx="205.1" cy="143.6" r=".25"/>
<circle cx="245.7" cy="156.3" r=".25"/>
<circle cx="266.3" cy="142.8" r=".38"/>
<circle cx="264.3" cy="143.8" r=".38"/>
<circle cx="265.3" cy="145.8" r=".38"/>
<circle cx="253.9" cy="79" r=".38"/>
<circle cx="252.9" cy="78" r=".38"/>
<circle cx="208.2" cy="139.7" r=".25"/>
<circle cx="267.3" cy="130.9" r=".25"/>
<circle cx="229.2" cy="131.6" r=".25"/>
<circle cx="218.6" cy="75.7" r=".25"/>
<circle cx="252.9" cy="79" r=".38"/>
<circle cx="252.9" cy="77" r=".38"/>
<circle cx="270.4" cy="151.9" r=".38"/>
<circle cx="226.2" cy="87.2" r=".25"/>
<circle cx="256.9" cy="76" r=".38"/>
<circle cx="241.4" cy="98.9" r=".25"/>
<circle cx="253.9" cy="80.1" r=".38"/>
<circle cx="253.1" cy="87.7" r=".25"/>
<circle cx="230.2" cy="127.6" r=".25"/>
<circle cx="264" cy="148.1" r=".38"/>
<circle cx="265" cy="148.1" r=".38"/>
<circle cx="253.9" cy="77" r=".38"/>
<circle cx="253.9" cy="78" r=".38"/>
<circle cx="253.9" cy="76" r=".38"/>
<circle cx="239.9" cy="77.5" r=".25"/>
<circle cx="226.2" cy="95" r=".25"/>
<circle cx="208.4" cy="118.4" r=".25"/>
<circle cx="252.9" cy="76" r=".38"/>
<circle cx="255.9" cy="76" r=".38"/>
<circle cx="255.9" cy="80.1" r=".38"/>
<circle cx="265" cy="149.1" r=".38"/>
<circle cx="256.9" cy="80.1" r=".38"/>
<circle cx="213.5" cy="71.4" r=".25"/>
<circle cx="269.1" cy="151.9" r=".38"/>
<circle cx="264" cy="149.1" r=".38"/>
<circle cx="254.9" cy="79" r=".38"/>
<circle cx="270.4" cy="150.7" r=".38"/>
<circle cx="208.7" cy="116.6" r=".25"/>
<circle cx="254.9" cy="80.1" r=".38"/>
<circle cx="222.1" cy="88.9" r=".25"/>
<circle cx="254.9" cy="76" r=".38"/>
<circle cx="270.4" cy="148.6" r=".38"/>
<circle cx="254.9" cy="78" r=".38"/>
<circle cx="257.9" cy="101.9" r=".25"/>
<circle cx="270.4" cy="149.7" r=".38"/>
<circle cx="252.9" cy="80.1" r=".38"/>
<circle cx="260.8" cy="124.8" r=".25"/>
<circle cx="215.3" cy="143.6" r=".25"/>
<circle cx="239.6" cy="84.6" r=".25"/>
<circle cx="218.3" cy="81.8" r=".25"/>
<circle cx="254.9" cy="77" r=".38"/>
<circle cx="219.7" cy="91.3" r=".25"/>
<circle cx="234.6" cy="91.7" r=".25"/>
<circle cx="226.4" cy="140.5" r=".38"/>
<circle cx="226.4" cy="129.1" r=".38"/>
<circle cx="216.3" cy="116.4" r=".38"/>
<circle cx="226.4" cy="131.1" r=".38"/>
<circle cx="274.2" cy="113.8" r=".38"/>
<circle cx="226.4" cy="136.2" r=".38"/>
<circle cx="226.4" cy="165.4" r=".38"/>
<circle cx="215.8" cy="114.6" r=".25"/>
<circle cx="254.6" cy="134.4" r=".25"/>
<circle cx="206.9" cy="129.1" r=".25"/>
<circle cx="208.4" cy="129.1" r=".25"/>
<circle cx="207.6" cy="129.1" r=".25"/>
<circle cx="201.3" cy="124.5" r=".25"/>
<circle cx="239.6" cy="117.9" r=".25"/>
<circle cx="251.6" cy="133.1" r=".25"/>
<circle cx="246.5" cy="124.3" r=".25"/>
<circle cx="263.5" cy="101.9" r=".3"/>
<circle cx="258.7" cy="135.4" r=".3"/>
<circle cx="240.6" cy="140.3" r=".25"/>
<circle cx="256.2" cy="123.2" r=".25"/>
<circle cx="264.3" cy="109.8" r=".25"/>
<circle cx="261.5" cy="102.9" r=".25"/>
<circle cx="265" cy="157.3" r=".25"/>
<circle cx="254.1" cy="145.1" r=".25"/>
<circle cx="250.6" cy="106" r=".25"/>
<circle cx="250.6" cy="102.9" r=".25"/>
<circle cx="245.9" cy="117.9" r=".25"/>
<circle cx="223.4" cy="96.1" r=".25"/>
<circle cx="218.6" cy="80.3" r=".25"/>
<circle cx="226.2" cy="103.9" r=".25"/>
<circle cx="242.5" cy="106" r=".25"/>
<circle cx="238.4" cy="106" r=".25"/>
<circle cx="250.8" cy="127.8" r=".25"/>
<circle cx="250.8" cy="116.6" r=".25"/>
<circle cx="238.1" cy="141" r=".25"/>
<circle cx="252.1" cy="140" r=".25"/>
<circle cx="233" cy="151.6" r=".25"/>
<circle cx="232" cy="154.7" r=".25"/>
<circle cx="249.6" cy="129.3" r=".38"/>
<circle cx="242.4" cy="128.8" r=".38"/>
<circle cx="247.3" cy="130.4" r=".38"/>
<circle cx="245.7" cy="128.8" r=".38"/>
<circle cx="259" cy="124.3" r=".38"/>
<circle cx="200.5" cy="117.1" r=".38"/>
<circle cx="252.3" cy="117.9" r=".25"/>
<circle cx="263.5" cy="116.6" r=".38"/>
<circle cx="249.5" cy="123.1" r=".25"/>
<circle cx="247.8" cy="123.2" r=".25"/>
<circle cx="204.3" cy="114.1" r=".3"/>
<circle cx="244.7" cy="80.1" r=".25"/>
<circle cx="234.1" cy="73.4" r=".25"/>
<circle cx="212.8" cy="85.6" r=".25"/>
<circle cx="212" cy="81.3" r=".25"/>
<circle cx="211.2" cy="77.3" r=".25"/>
<circle cx="213" cy="88.7" r=".25"/>
<circle cx="231.5" cy="138" r=".25"/>
<circle cx="242.5" cy="134.9" r=".25"/>
<circle cx="220.7" cy="139.6" r=".25"/>
<circle cx="250.1" cy="139" r=".25"/>
<circle cx="258.7" cy="100.3" r=".25"/>
<circle cx="240.7" cy="77.3" r=".25"/>
<circle cx="244.2" cy="82.6" r=".25"/>
<circle cx="249.8" cy="92.5" r=".25"/>
<circle cx="234.8" cy="80.1" r=".25"/>
<circle cx="233.8" cy="79" r=".25"/>
<circle cx="257.2" cy="100.3" r=".25"/>
<circle cx="236.6" cy="81.3" r=".25"/>
<circle cx="240.9" cy="81.3" r=".25"/>
<circle cx="245.5" cy="93" r=".25"/>
<circle cx="235.1" cy="73.5" r=".25"/>
<circle cx="220.9" cy="86.2" r=".25"/>
<circle cx="214.5" cy="75.2" r=".25"/>
<circle cx="225.7" cy="89.5" r=".25"/>
<circle cx="209.2" cy="77.8" r=".25"/>
<circle cx="226.4" cy="72.6" r=".25"/>
<circle cx="230" cy="71.9" r=".25"/>
<circle cx="219.1" cy="71.9" r=".25"/>
<circle cx="222.9" cy="82.3" r=".25"/>
<circle cx="214.5" cy="74" r=".25"/>
<circle cx="203.1" cy="139.2" r=".25"/>
<circle cx="249.4" cy="138.7" r=".25"/>
<circle cx="228.7" cy="107.7" r=".25"/>
<circle cx="225.4" cy="103.2" r=".25"/>
<circle cx="225.2" cy="162.6" r=".25"/>
<circle cx="218.8" cy="161.8" r=".25"/>
<circle cx="258.7" cy="152.4" r=".25"/>
<circle cx="225.7" cy="163.6" r=".25"/>
<circle cx="257.4" cy="153.7" r=".25"/>
<circle cx="232" cy="157.3" r=".25"/>
<circle cx="252.5" cy="142.3" r=".25"/>
<circle cx="247.8" cy="149.1" r=".25"/>
<circle cx="251.6" cy="159.6" r=".25"/>
<circle cx="254.4" cy="143" r=".25"/>
<circle cx="253.1" cy="144.3" r=".25"/>
<circle cx="244" cy="105.2" r=".25"/>
<circle cx="232" cy="153.5" r=".25"/>
<circle cx="228" cy="153.5" r=".25"/>
<circle cx="255.4" cy="143" r=".25"/>
<circle cx="253.4" cy="145.1" r=".25"/>
<circle cx="248.3" cy="158" r=".25"/>
<circle cx="245.7" cy="157.8" r=".25"/>
<circle cx="250.6" cy="154.3" r=".25"/>
<circle cx="248.8" cy="157" r=".25"/>
<circle cx="251.3" cy="150.7" r=".25"/>
<circle cx="249.8" cy="149.1" r=".25"/>
<circle cx="249.1" cy="149.4" r=".25"/>
<circle cx="254.4" cy="141.3" r=".25"/>
<circle cx="245.4" cy="112.6" r=".25"/>
<circle cx="238.6" cy="101.4" r=".25"/>
<circle cx="233.3" cy="102.2" r=".25"/>
<circle cx="241.9" cy="102.9" r=".25"/>
<circle cx="248.8" cy="137.2" r=".25"/>
<circle cx="259.7" cy="115.4" r=".25"/>
<circle cx="226.4" cy="91" r=".25"/>
<circle cx="234.8" cy="84.4" r=".25"/>
<circle cx="226.9" cy="86.4" r=".25"/>
<circle cx="226.9" cy="79.5" r=".25"/>
<circle cx="261" cy="114.9" r=".25"/>
<circle cx="248.1" cy="137.5" r=".25"/>
<circle cx="233.8" cy="81.5" r=".25"/>
<circle cx="233" cy="75.7" r=".25"/>
<circle cx="214.8" cy="114.3" r=".25"/>
<circle cx="216.8" cy="129.1" r=".25"/>
<circle cx="254.4" cy="138.3" r=".25"/>
<circle cx="227.7" cy="140.5" r=".25"/>
<circle cx="251.6" cy="164.1" r=".25"/>
<circle cx="256.4" cy="162.9" r=".25"/>
<circle cx="225.4" cy="74.7" r=".25"/>
<circle cx="234.8" cy="82.1" r=".25"/>
<circle cx="214" cy="125.5" r=".25"/>
<circle cx="209.2" cy="127.3" r=".25"/>
<circle cx="230" cy="100.1" r=".25"/>
<circle cx="256.4" cy="99.6" r=".25"/>
<circle cx="262.8" cy="104.9" r=".25"/>
<circle cx="240.3" cy="121.3" r=".25"/>
<circle cx="244.5" cy="136.9" r=".25"/>
<circle cx="235.1" cy="122.7" r=".25"/>
<circle cx="235.1" cy="120.7" r=".25"/>
<circle cx="261.7" cy="142.5" r=".25"/>
<circle cx="269.9" cy="125.3" r=".25"/>
<circle cx="262.5" cy="143" r=".25"/>
<circle cx="269.9" cy="126.1" r=".25"/>
<circle cx="240.9" cy="109" r=".25"/>
<circle cx="213" cy="100.9" r=".25"/>
<circle cx="213.2" cy="106.5" r=".25"/>
<circle cx="241.7" cy="116.1" r=".25"/>
<circle cx="242.9" cy="102.9" r=".25"/>
<circle cx="213.7" cy="101.6" r=".25"/>
<circle cx="215.8" cy="88.2" r=".25"/>
<circle cx="215.8" cy="84.8" r=".25"/>
<circle cx="238.1" cy="154.2" r=".25"/>
<circle cx="238.1" cy="151.7" r=".25"/>
<circle cx="200.5" cy="115.1" r=".38"/>
<circle cx="235.6" cy="166.9" r=".38"/>
<circle cx="227.5" cy="137" r=".25"/>
<circle cx="219.3" cy="136.4" r=".25"/>
<circle cx="206.3" cy="128.3" r=".25"/>
<circle cx="251.6" cy="145.8" r=".25"/>
<circle cx="252.3" cy="148.6" r=".25"/>
<circle cx="254.9" cy="145.8" r=".25"/>
<circle cx="247" cy="142.3" r=".25"/>
<circle cx="247" cy="143.8" r=".3"/>
<circle cx="252.6" cy="137.1" r=".25"/>
<circle cx="238.4" cy="106.7" r=".25"/>
<circle cx="237.4" cy="108.5" r=".25"/>
</g>
<g fill="none" stroke="#c83434" stroke-width=".3">
<path d="M207.7 76.5h1.2l1.9 1.9h3l1.7 1.7h2.5l.4-.4h7.9l.6 .6h1.5M207.7 79h1l3 3.1h1.9l.7 .8M207.7 77.8h1.5M212 76.5l-.8 .8M212.7 74h1.8M212.7 75.2h1.8M213.2 79l1.6 1.6h3.1l.5 .5h11.8l.8-.8M214.9 71.9l-.5-.5h-.9l-.8 .8v.5M215.9 79h1.4M217.5 79h6M219.1 71.9l-5.9 5.9M220.3 71l.9-.9h1.3l.4 .4v2.2"/>
<path d="M220.3 74.5l.8 .7h2.4M220.4 72.8l1.1 1.2h3.1l.8 .7M222 70.9l-1 1h-1l-.4 .5v1.5l.5 .6M222.9 76.5l-.5 .5h-1.2l-1.3-1.3h-2.8l-1.3 1.4M223.8 71.1l2.1 2.1h1l.8 .8-1.3 1.2v1.6l1 1h1M224.2 72.7l1.7 1.8v1.8l-1.5 1.5h-.9M225.4 74.7h.1M226.4 72.6l2 .1M228.4 75.2h4.1l.5 .5M230 71.9l.9 .8M231.6 74h3l1.2 1.2-2.5 2.6h-1.7M231.6 79h-4.1l-.6 .6"/>
<path d="M233.8 79l-.8 .8v.7l-1.1 1.1h-3.4l-2.4 2.4h-3.4l-.9-.9h-.9l-1.1 1M234 73.4h-3.9l-.6 .6h-1.1M234 73.4h.1M235.8 77.8l-2 2.3v.5M235.8 72.7l-.7 .8M236.5 76.5h1.8l1 1h.6M237.4 75.2l.7 .8h1.3l1.3 1.3M238.6 79.1h6.4l4.7 4.8v1.2M246.3 78l-1.1-1h-2.2l-1.2 1.2h-3.9l-.8 .8M246.3 72.4l-1.6 1.6h-8.2M207.5 95.6h1.2l6.1 6.1v12.6M207.5 98.6h3.4l2.1 2v.3"/>
<path d="M212.7 80.3l-.7 .7v.3M212.8 85.6l1 1.1M213.7 82.9l-1.5 1.5v13.3l2.2 2.2M213.7 87.9l-.7 .8v6.9l1.2 1.2M214.3 86.7h1l1.2 1.2v5.5l-.3 .4M214.3 85.4h2.1l2.5 2.5M214.4 93.8l1 1h1.5l1-1M215.1 84.1l.7 .7M215.8 88.2l-1 1M216.2 96.8h2M216.2 99.9h1.7M218.3 81.8l1 1"/>
<path d="M219.3 90.5v.4l.4 .4M219.8 89.2l1.1 1v12.1l-1.2 1.1M220.1 86.7l.8 .7v2.2l.4 .4v11.6l1.1 1.1M220.1 85.4l.8 .8M221.4 84l-.5 .5v.6h.3l.7 .7M221.4 82.2h-1.5l-.6 .7M221.9 87.5v1.2l.2 .2M222.9 82.3l1.1 1.1M223.4 96.1l1 1v3.5l-.7 .8M223.5 80.3h-4.9M223.5 93.8l1.3 1.2h2.3l1 1.1M224 87.2h2.2"/>
<path d="M225.7 89.5v.4l-1 1.1M226.2 88.5h-.3l-1.2 1.2M226.2 88.5l.2 .2v2.3M226.9 86.4v1.3l-.7 .8M227.9 96.3v1.3M227.9 98.9h4.9l1.3 1.3h2l1.9 2h2.1M228.3 89.7l-1.2 1.3v2.8h-1.8M228.9 88.4h1.5M228.9 91h1.2l3.9 3.8h3.1l1.5 1.5v4.1l.5 .5M230.4 88.4l1.8 1.8v1.2l1.1 1.1h3.6l1.1-1.2v-1.1M232 94.9v1.8M233.7 86.7h-1.5l-1.8 1.7"/>
<path d="M233.8 80.6l-1.5 1.5h-3.7l-2.6 2.5h-2.6l-.7 .7v2.6l.5 .5M233.8 80.6l.8 .7h2M233.8 81.5v2M234.8 80.1l.3 .2h1.4M236.1 90.2l-1.5 1.5M237.4 83.6l-1.5 1.4h-1.4l-.5-.5v-.9l-1.1 1h-2.4l-.6 .7h-4.6l-.6 .6M238.6 81v.8l-.2 .3h-3.6M239.2 83.6v.6l.4 .4M240.1 99.6l.8-.7h.5l.9 .9M240.2 86.7h-3.7v3.2M240.9 81.3h.5l.5 .5v6.1l2.3 2.3M241.1 83.6l-.8-.8h-3.8l-1.7 1.6"/>
<path d="M244.2 82.6v1l.3 .3M244.7 80.1l3.8 3.7v6.1l.3 .3h.9v1.3M244.8 83.9v1.2h1l2.2 2.3v4.3l.8 .8h1M244.8 88.9h1l.5 .5v5l-.5 .4h-1.7M244.8 90.2v2.1l.7 .7M245.5 86.4l1.3 1.3v9.2l-1 .9h-1.7M249.7 88.9h1l.3 .4v.8l2.7 2.7h4.3v-.7l1.8-1.7M249.7 86.4h8.1M253.1 87.7l-3.2 .1M254.5 98.3v2.6M256.4 99.6h.1M256.4 99.6h2.8l3.6 3.6v1.8"/>
<path d="M257.9 84.3v1.8M259.9 87.7h5.1l1.9 1.9M260 86.3v1.3M266.8 92.8h-6.9v2M266.9 95.6h3.5l.7 .7v28.6l-1.2 1.2M266.9 98.6h2.9l.9 .8v25l-.8 .9M269.4 94h-7.1l-2.8 2.8h-9.1l-1 1h-1.7M269.4 91.1h-9.3l-1.3 1.3v.8l-.8 .8h-6l-1.6 1.6h-1.9l-.8-.8M269.4 97.1h-7l-2.1 2h-1.5l-.8-.8h-1.7M199.7 101.6l.8 .8v1.3l.5 .5v.7l-.5 .5v1.3l.5 .5v.8l-.5 .5v1.2l.5 .5v2.1l-1.2 1.3v5.2l1.9 1.9-2.2 2.1v3.2l-4 4.1v2.5M203.5 118.2h1.7l1-1.1h2.2l.5 .6h5.9l1 1M204.3 115.4l-1.7 1.8v5.1l-2.3 2.4v1.8l-2.6 2.6v3.5"/>
<path d="M204.3 114.1v1.3M204.3 115.4h.1M204.3 115.4h8.2l1.7 1.7h.8l.5 .6h9.2l1.2 1.2v1.3l1.1 1.1h12.2l1.9 1.9h6.7M207.6 101.6h6.1M207.6 107.5h5.9l.3 .3M207.7 104.7h3.8l1.7 1.8M208.4 118.4l1 .8M208.5 110.7l6 5.9h.8l.5 .5h9.9l1.8 1.9v.7M208.7 116.6h1.1M213.2 119.9l-1.5 1.6h-5.8l-.7-.7M214 108.1v2.3M214.5 119.9l1.8 1.8h2.6"/>
<path d="M215.8 110.6v2.3M215.8 113.2v1.4M217.1 119.2h1.8M217.8 103.5v1.8M219.7 103.6l.4 .3h2.8M220.7 119.2h2.1M227.2 102.7l-1 1v.2M227.2 101.4l-1.8 1.8M227.9 100.1h2.1M228.5 103.9l2.4-2.3h5.3l1.8 1.8h3.4l1.8 1.8h.8M229.5 110.2l1.1 1.1h3.8l.7-.6M230.1 104.3l-.3 .2h-4.6l-4.9 5h-1"/>
<path d="M231 107.2l-.5 .5h-1.8M231.4 119.7h-.6l-1 .9M232 106.6v2.9M233.3 102.2h-.8l-1.5 1.5M235.1 104.7h-.9l-.8 .7h-5.3l-.2-.2M235.6 104.7l5.4 5.4v6.6l3.8 3.7v.3M235.8 106l4.4 4.3M236.1 118.5h2.5M237.4 108.5l-2.2 2.2M238.4 106h1.7M239.1 100.9h2l.8 .9v1.1M239.1 100.9l-.5 .5"/>
<path d="M239.6 117.9v-.3l-1-1-1 1.1h-2.4l-2 2M240.1 107.2h6.8l2.3 2.4v.7M240.1 104.7h1.8l1.3 1.3h5l.7-.8M240.2 110.5v7.7l-1.2 1.2h-3.2l-.7 .6v.7M240.2 106h2.3M240.9 109h2.6M242.9 102.9l.6 .6v.4M244 115.4h-1.6l-.7 .7M245.4 112.6l1.3 1.2h.9M245.4 110h1.7l.3 .3M245.4 104.9h1.9M245.9 116.3l.3 .3h1.7"/>
<path d="M245.9 117.9h.1M246 117.9l1 1h1.4l1.3 1.3v.5M247.5 119.7l-.7 .7v1.8l-.4 .4h-1.8l-.8-.8M247.9 114.1l1.8 1.8v.7l.7 .7h8.7l.8 .8M249 103v2.1M250.6 102.9v3.1M252.3 117.9v1.6l-4.2 4.2h-10.4l-1.6-1.6h-5.2l-3.2 3.2v.9l-3.1 3.1M255 100.9h.6l1.1 1v6.9l-5.9 5.9v1.9M255.4 105.5l-1.2 1.1-15.8 .1M257.2 100.3v7.8l.8 .9M257.9 101.9l.1 1M258 118.1v2.6"/>
<path d="M258.7 100.3l.3 .3v10.4l-1.1 1M259.7 114.6v.8M259.8 112v2.6M259.9 105.9v3.8l1.1 1.1v4.1M259.9 102.9h1.6M263.5 101.9v8.1l.8 .8v7.1l-6.1 6.1v8l1.3 1.3v1.3l-.8 .8M267.1 110.7v10.6l-3.4 3.4v1.7M269.1 109.4v1.9l-1.3 1.3v9.8l-1.8 1.9v.3l-1.1 1.1M269.4 100.1h-3.3l-1.8 1.8v7.9M272.7 109.3v18l-2.1 2v2M274.9 110.6l-1.7 1.7v16.3l-.7 .7M201.3 124.5v1.1"/>
<path d="M201.5 125.8l-2.2 2.4v6l-1.6 1.5M201.8 133.5l-.8 .8v2.3l.8 .8v2M202 139.2h1.1M203.5 120.7h1.7M203.5 123.2h1.7M203.5 125.8h1.7M205.2 125.9l1.4 1.4h2.6M205.2 123.1l.9-.9h4.6l1.3 1.3M205.6 136.4h-1.3l-.4 .4v4.6M205.6 131.4h-1.3l-.3 .3h-2.2M206.3 128.3h2.1l1.6 1.6v5.2l-.6 .6M206.9 129.1l-.7 .6v5.3l.7 .7"/>
<path d="M207.6 129.1v.5l-.7 .8v1M208.2 136.4v1.7l-.4 .4 .4 .3v.9M208.4 129.1l1 1v1.3M209.4 124.2v2.2l1.9 1.9h8.4l1 1h2M210.7 131.4h1.3v1.1l1.7 1.8M210.7 124.2v2.2l.3 .4M210.7 136.4h1.3l1.4 1.5M212.9 126.8h2M213.2 123.5l.8-.8h3.4l1.5 1.5M213.8 135.9h3.8M213.9 132.6h3.8M214.5 125l-.5 .5"/>
<path d="M215.8 125l2.1 1.8h1M216.6 126.8l.8 .8h.4M216.8 129.1l5.1 5.2v3.2l3.8 3.8h1.2l.8-.8M217.9 132.6h1.4l.9 .9v5.6l.5 .5M218 135.9h.8l.5 .5M220.7 121.7h2.1M220.7 126.8h2.1M220.8 124.3h2M227.5 137h3.8l1.8 1.7h4l3.1 3.1h5.5M228 134.8v.4l.9 .9h1.7l.8-.8M229 127.7h1.1M230.1 130.7l-.9 .9h-.7l-.5-.5"/>
<path d="M231.4 129.6l-.9-1h-1.9l-1.4 1.4v2.2l.8 .8M231.5 138l-4.3 4.3h-15.2l-.9-.9h-1.8l-1.1 1.1h-1.3l-1.1-1.1M232.1 127.7l.6 .6v2.6l-1.3 1.3v2.7M233.9 127.7v2.2M235.1 122.7v11l-1.2 1.2M236.1 120.3h2.5M237.2 130.4v3.7l-2.1 2.1h-1.8l-.6-.6M238.7 120.3h.5l1.1 1M239 130.4h2.2M241.3 125.3v2.6l-1.7 .2-1.5 1.5v9.4l2.3 2.3h5.3M242.5 134.9l3.5-3.5h3.3l.8 .7v3.8M242.5 134.9h.1"/>
<path d="M243.1 131.4v.6l-3.2 3.2v4.4l.7 .7M243.3 124.9l-.4-.4h-2.6l-.8 .8M243.9 138.8h1.8M244.4 135.4l-.8 .8v2.3M244.5 136.9l.9 .9M244.8 120.7h-2.6l-.5 .5M244.8 120.7l1.1 1.1M245.7 139.3h1.5l3.8 3.8h2.4l4 4v1.2l.5 .6v4.3l2.1 2h4.5l1-.9h3.1M245.7 139.8h1.1l3.8 3.8h2.5l1 1v.5M246.5 124.3l-1.3 1.5M247 138.2l-1.3 .1M247.6 124.5h.6l.8-.8h1.8l.6 .6v.5"/>
<path d="M248.1 135.9v1.6M248.1 137.5h.1M248.6 135.9v1.1l.2 .2M248.6 133.9l.5 .4v1.6M248.6 133.9l-.7 .8h-1l-.8 .7M248.6 132.4v1.5M249.4 124.5v.7l-1.8 1.8v1.3l-7.2 7.2v3.7l1.5 1.6h3.8M250.6 135.9v1.6l-1.2 1.2M250.8 127.8l-.5 .5h-2l-7.3 7.3v3.5l1.2 1.2h3.5M251.1 135.9v2.1l-1 1M251.3 130l.9 .8h1M251.5 131.9h1.7l-.6 .6v3.4"/>
<path d="M251.6 134.9h.1M251.6 133.1v2.8M252.1 135.9v4.1M253.1 129.4v1.4M253.2 130.8l1.1 1.1M253.6 135.9v.8l-.4 .4h-.6M254.1 135.9v2l.3 .4M254.6 129.5v1.3M254.6 134.4v1.5M254.6 135h.1M254.6 130.8l.7 .7v.8l-.5 .6h-1.2l-.5 .5v2.5M255.4 120.7l-2.5 2.4h-3.4"/>
<path d="M256.2 123.2l-2.6 2.6M256.3 132.9l-.2 .3v.7l-1 1v1M257.9 135.4l-.3 .4v.6l-.6 .6v.8M257.9 120.7l-1 1v14.1l-1 1v1.7l-2.3 2.3h-4.3l-1.7-1.8v-3.1M259.5 131.7v.9l.2 .3h.5l.9-.9M259.5 125.9l1.3-1.1 .3 .3v1.3M262.1 137v1.6l-1.2 1.2h-3.9M262.4 131.3v2.1l-1.7 1.7v3.4l-.3 .3h-3.4M263.5 134.7l-.5 .5v3l-2 2.1h-4M263.7 131.3v1.5l-2.5 2.4v3.5l-.5 .5-3.7 .1M267.3 129.4v1.5h.9M268.2 136.4v.9l-.6 .7h-.5l-.5-.5v-.7"/>
<path d="M269 129.3l.5 .6v1.5M269.5 136.4v1.2l-3.2 3.2h-9.3M270.8 137.1l-4.2 4.2h-9.6M272.2 129.3l-.2 2.1M205.1 143.6v1.6M215.3 143.6l-.1 1.6M217.8 159.8v1l1 1M228 153.5v3.4l-5.2 5.2h-1.4l-1.1-1v-1.3M229.2 157.3l-5.8 5.8h-12.4l-2.1-2.1v-1.2M229.2 158.5l-4 4.1M229.2 153.5l-.7 .7v3.1l-5.4 5.3h-5.6l-1-1v-1.8M230.1 154.7h1.9"/>
<path d="M230.1 157.3h1.9M234 157.3v1.2M234 159.8h2.1M234.1 143l-1.1 1.1v7.5M236.1 143h-31.3l-1 1v1.2M236.3 142.7h.1M238.1 141l-1.7 1.7M238.1 141h.1M238.1 154.2v2.5M238.1 156.9v2.8M243.6 147.1v.4l-.7 .6M245.7 145.3l-1.9 1.8"/>
<path d="M245.7 143.3h-1.3l-.8 .8M245.7 144.3h-.9l-1.2 1.3M245.7 143.8h1.3M245.7 142.8h-5.2l-2.4 2.4v6.5M245.7 142.3h1.3M245.7 153.4l1 .9h.4M246 157l1.1 1.2v.9M247 143.8h.1M247.1 155.9l-1.1 1.1M247.1 152.5v1M247.1 155.1h-.9l-.5 .5v.7M247.3 151.2l.1 1"/>
<path d="M247.6 147.2v1.1l-3.4 3.4v5.1l1 1h.5M248.1 147.2v1.6l-.3 .3M248.3 158l.2 .9M248.6 147.2v2.2l-.6 .5h-1.2l-2.1 2v4.6l.5 .5h.8M248.8 157h-.8l-.4 .5v.8l.4 .4M249.1 147.2v1.2l.7 .7M249.1 149.4l1 .9v3.7l-.6 .3M249.1 149.4h.1M249.5 152.5v1M250.1 147.2v1.2l.5 .5v5.4l-.9 .8h-.2M250.6 147.2v.9l.5 .5v.8l1 1v4.1l.5 .5v4.6l-1.5 1.5h-.6M251.1 147.2v.8l.5 .5v.6l1 1.1v4l3 3.1v6.3l-3.8 3.8h-1.6"/>
<path d="M251.3 150.7v3.6l-1.6 1.6h-.2v2l-.5 .5v.5M251.6 145.8v1.4M251.6 159.6h-1.1M252.1 147.2v1.2l.2 .2M252.5 142.3h.1M253.1 144.3h-4.8l-8.4 8.4h-8.1l-.8 .8M253.1 144.3h.1M253.1 147.2h.1M253.1 147.2v6.8l3.3 3.3v5.5M253.4 145.1h-5.1l-8.4 8.4h-7.9M253.6 147.2h.1M253.6 147.2v5.2l.8 .8"/>
<path d="M254.1 147.2v3.9l2.8 2.9v10.4l-4.3 4.3h-19l-1.8-1.8v-6.7l-.4-.4h-2.7l-3.8 3.8h-16.5l-2-2v-1.8M254.4 143.1l1.2 1.2h1.4M254.4 141.3l.5 .5h2.1M254.9 145.8h-2l-.3 .3v1.1M255.1 147.2v1.1l.5 .6h.6l.3-.3v-1M255.4 143.1l.7 .7h.9M257 142.3h-4.5M257 145.3h1.1l1.1 1.1v5.5l-.5 .5M257 144.8h3.2M257.4 153.7v10.9l-4.5 4.6h-21.6l-5.6-5.6M261.7 142.5l-.2 .3h-4.5M262.5 143.1l-.2 .2h-5.3"/>
<path d="M265 157.3l1.1 1.1h2.5M267.6 150.3l-.4 .4M279.2 154.5h-.9l-4.9 4.8h-6.4l-.9 .9h-2.1M279.2 152.5l-5 5h-6.8l-1.3-1.3h-2.1M242.8 163.6h1.8M243 160.3h1.6M244.7 160.2v1.1l.8 .8h1.6M246.3 163.1h.1M247.1 163.1h-.8M247.1 162.6h-1.5l-.9 .9M248 163.8l-.2 .6h-.8M248.1 165.4l-.6 .6v.6l.9 .8"/>
<path d="M248.5 163.8v1.6M249 163.8v2.3l1.2 1.2M249.5 163.8v1.1l1.1 1.1v.4M250.4 163.6h.4l.8 .5M250.5 162.1h.8l1 1M253.3 165.9v.1M253.6 165.6h.1M256.4 162.8v.1"/>
</g>
<g fill="none" stroke="#c83434" stroke-width=".51">
<path d="M256.7 79.8l.2 .3M265 77.7l.3 .3v2M266.8 76.8h3.6l2.3 2.2v8.8M199.5 95.6h3.6l.5 .5v18l-3.1 3 1 1.1M267.1 86.4h5.6M205 100.1v9h4.7l1.5 1.5v1.7l3.3 3.3h6.9l5.5-5.6 5.1 5.1M216.3 116.3v.1M216.3 115.6v.7M255.4 113.1v1l2.5 2.5h5.6M266.9 101.6l-1.9 1.9v15.9l-4.8 4.9h-1.2M274.2 113.8l.2 .3v18l7.9 7.9v16l-1.5 1.5 1.5 1.6v7.3l-3.5 3.6h-47.8l-4.6-4.6M226.4 129.1v2"/>
<path d="M226.4 136.2v4.3M242.4 128.8h3.3M249.6 129.3h-1.3l-1 1.1M240.1 159.8v.9l-1.4 1.3v.9M267.6 148.8v1.5M238.7 164.8v.6l-1.5 1.5h-1.6"/>
</g>
<g fill="#c83434">
<path d="M191.3 161.6l10.3-.1v-2.9l.4-.1-.1 2.4h4.1l.1 .9 2.3 2.1 16.8-.1 1.1 1a.61 .61 0 0 0-.4 .6 .61 .61 0 0 0 .5 .6l4.6 4.4h47.8l3.9-3.7 .1-7.7-1.1-1.2v-.5l1.1-1.3v-16.1l-7.9-8v-18a.73 .73 0 0 0-.6-.6 .73 .73 0 0 0-.8 .3v-1.2l.8-.7a1.23 1.23 0 0 0 1.8-.9 1.23 1.23 0 0 0-1.4-1.4 1.23 1.23 0 0 0-.9 1.8l-.8 .7v-1.8a1.25 1.25 0 0 0 .3-1.8 1.25 1.25 0 0 0-1.9-.1v-.7h2.4a1.18 1.18 0 0 0 1.6 1.2 1.18 1.18 0 0 0 .3-2 1.18 1.18 0 0 0-1.9 .7l-2.4 .1v-.5a1.23 1.23 0 0 0 2-.3 1.23 1.23 0 0 0-.9-1.8l-1 .3-.1-.7h2.4a1.18 1.18 0 0 0 1.6 1.2 1.18 1.18 0 0 0 .3-2 1.18 1.18 0 0 0-1.9 .7l-2.4 .1v-.5a1.23 1.23 0 0 0 2-.3 1.23 1.23 0 0 0-.9-1.8l-1 .3-.1-.7h2.4a1.18 1.18 0 0 0 1.6 1.2 1.18 1.18 0 0 0 .3-2 1.18 1.18 0 0 0-1.9 .7l-2.4 .1v-.5a1.23 1.23 0 0 0 2-.3 1.23 1.23 0 0 0-.9-1.8l-1 .3-.1-.7h2.4a1.18 1.18 0 0 0 1.6 1.2 1.18 1.18 0 0 0 .3-2 1.18 1.18 0 0 0-1.9 .7l-2.4 .1v-.5a1.23 1.23 0 0 0 2-.3 1.23 1.23 0 0 0-.9-1.8l-1 .4-.8-.8h3.1v.2a1.18 1.18 0 0 0 1.8 .9 1.18 1.18 0 0 0 0-2 1.18 1.18 0 0 0-1.8 .9h-3.1l-.6-.2 .5-1.3h.7a1.18 1.18 0 0 0 1.6 1.2 1.18 1.18 0 0 0 .3-2 1.18 1.18 0 0 0-1.9 .7l-.7 .1a1.23 1.23 0 0 0-1.1-1.1 1.23 1.23 0 0 0-1.3 .8l-.6-.1 .5-1.1h5.7a1.18 1.18 0 0 0 1.6 1.2 1.18 1.18 0 0 0 .3-2 1.18 1.18 0 0 0-1.9 .7l-5.7 .1-.5-1 .7-.1a1.2 1.2 0 0 0 1.9 .5 1.2 1.2 0 0 0-.2-2 1.2 1.2 0 0 0-1.8 .9l-.6-.2a1.57 1.57 0 0 0 .4-1.6l.8-.6 .4 .3-.6 .7a1.5 1.5 0 0 0 1.7-.1l-.6-.6 .4-.3 .6 .5a1.5 1.5 0 0 0 0-1.7l-.6 .6-.4-.4 .6-.6 1.6 .1a1.29 1.29 0 0 0-.3 2 1.29 1.29 0 0 0 1.9-.1l-.1 1.6a1.2 1.2 0 0 0-2 .1 1.2 1.2 0 0 0 1.1 1.8 1.2 1.2 0 0 0 1-1.8l.8-.6 .4 .3-.6 .6a1.49 1.49 0 0 0 1.7 0l-.6-.6 .4-.3 .6 .5h.3v35.9l.2 .2 5.4 .1 .7 .3 .4 .7v41.9a1.27 1.27 0 0 1-1.3 1.2h-89.4l-.9-.3-.3-.7z"/>
<path d="M257.9 153.8l1.9 1.7 3.6 .1 .1 1.1 .9 .1 .3-.3h.6l.4 .3h.6l1 1 .7 .2-1.2 .1-1.3-.7a.53 .53 0 0 0-.5-.6 .53 .53 0 0 0-.5 .6h-.2v.7l.9-.1 .4 1 1.1 .2-.4 .3-1.5 .4-.4-.4 .5-.4 .1-.5h-2l.2 .5 .5 .4-.3 .4 .1 .9 .9 .1 .3-.4h.6l.4 .4h.6l.4-.4h.9l.4 .6 1 .1 .4-.3 .2-.5h-.7v.8h-.6v-.8l-1.6 .1v-.5l.4-.4 .5 .1v.2h2l.1-.3h3.8l4.9-4.7 .3 .4-.1 .2 .6 .6-.4 .4-.6-.7-.2 .6 .2 .8 .6-.6 .4 .3-.6 .6 1.3 .2 .3 .5 .8 .2 .9 .9v2.8l-.6 .6-.4-.4 .6-.5-.3-.2a1.85 1.85 0 0 0-1.9 .2l.6 .5-.4 .4-.6-.5a1.85 1.85 0 0 0 0 2.2l.6-.6 .4 .3-.5 .7a1.85 1.85 0 0 0 2.1-.1l-.6-.6 .4-.3 .6 .6v1.9l-3.3 3.2h-25.4l4.5-4.7v-6.7h6.1v-.7l-.5 .2-.3 .5h-5.3z"/>
<path d="M234 154.5h1.7l-.1-.7h2.2v2.3l-.2 .9 .2 .5v1.6l-.2 1 .2 .4h.8l.3-.3v-.8l-.5-.3v-.5l5.3 .1-.2-.5-.5-.3-.1 .8h-.5v-.8l-.4 .2-.3 .5h-3.3v-1.1l.5-.4 .6 .6h.9l.5-.2 .1-.4-.7-.1v.7h-.5v-1.2h1.2v-.3l-.6-.4-.1 .7h-.5v-.7l-.5 .1-.3 .5-.5-.3v-2.2l1.6-.2 7.1-7 .1 1.5-3.4 3.4v5.2l1.2 1.3a.85 .85 0 0 0 1.2-.3l.5 .4v.4l-.3 .3 .1 1.9-.4 .6h.8v.3l-1.4 .1-.3-.3 .5-.6v-1.4l-.2-.3h-3.9l.5 .8-.2 1 .2 .3 .9 .1 .3-.7 .2-.1 .2 .6 .6 .1 .8 1-1.3 .2-.3 .8-.5-.5h-.8l-.3 .8-.6-.5h-.6v1.6l.8-.2 .1 .5h2l-.4-.9a.25 .25 0 0 1 .3-.2 .25 .25 0 0 1 .1 .4l.3 .2h1.5l-.1 .6h.8v-.7l-.4-.1v-.8l1.5 .4 .5 .8-.4 .2-.7-.5v2h.4l.6 .8 .1 .7 .9 .2 .3-.3v-.9l-1-.4-.1-.4 .6-.1 1 1.1 .1 .8 .9 .2 .5-.4h1l3.9-3.9 .1-.5 .6 .1v.9l-4.2 4.1h-18.7l-1.4-1.4h2.7a.59 .59 0 0 0 1 .4h.4l.2 .3 2.3-.1 .4 .4a1.62 1.62 0 0 0 1.8-.2v-.6h-.8v.8h-.5v-.8h-.9v.4h-.9v-.9l.8-.7 .1 .7h2.2v-.6l-.4-.3h-.4v.9h-.5v-.9l-.6 .1-.1-.3h2.6l.3 .5 .4 .2 .8-.1 .5-.5h1.7l.2 .5 .5 .2 .1-.7h-2.5v-.2h-.8v.8h-.5v-.8l-3.3 .1 .5-.4 .1-.5h.6v-.6h-1v.2l-1.5 .2v.6l.3 .3-.7 .7-.8 .1-.3 .3-.9-.1-.4 .6h-2.7l-.2-.2v-4.1h5.7l.2 .7 2.3 .2v-.5h-.6l-.1-.5-.5-.3 1.4-1.5 .2-1.3-.3-.3-.9 .1-.1 .8 .2 .4-1.2 1.3-.1 .6-.5 .3h-5.7v-2.5l-.8-1 .1-.2h.9l.3 .4 .1 2.2h2.5v-1.2l.5-.3a.48 .48 0 0 0 .7-.1 .48 .48 0 0 0-.1-.7 .48 .48 0 0 0-.7 .2l.1-.7-4.3 .2-.1-1.1 .2-.3 .8 .1v.6h3.4v-.8h-1.5v.8h-.5v-.9l.4-.4h1.6l-.3-.7v-.6l.3-.7h-1.6z"/>
<path d="M252.9 155.2l2.4 2.2v6l-2.4 2.5-.2-.2h-.8v.7l.4 .1-.6 .6h-.8l-.1-.2 .2-.5h.4l.1-.9 .3-.3 .9-.1-.1-.4-.6-.4v-.3l.9-.2v-1.3l.4-.6v-.2l-2.9-.1 1-.4h1.9l-.1-.5-.6-.3v.8h-.5v-.7l.8-.9z"/>
<path d="M207.4 159.9h.5v1.4l.7-.2 1.9 2.2h-2l-1.8-1.8v-.3l.7 .1z"/>
<path d="M209.4 160.9h1l.3 .3 .5 .1v-1.4l.4-.1 .1 1.5 .5-.1 .3-.3h3.6l.1 .8 .9 1-5.9 .1z"/>
<path d="M223.1 143.3h5l.4 .3 1.2 .1 .5-.4h3l-.5 .7v7.3a.46 .46 0 0 0 0 .6 .46 .46 0 0 0 .7 0 .46 .46 0 0 0-.1-.6v-4.1h.5a1.39 1.39 0 0 0 1.9-.6v-.2h-1v.8h-.6v-2h.6v.7h1l-.1-.5h1.3l.4-.7h-.7v.8h-.5v-.8h-.7v.6h-1.9l-.1-1.1 .5-.5 1.1-.1 .4-.3 .3 .1-.3 .8h1.9l-.4-.8 .1-.9 1.5-1.2 .1-.5 1.5 1.3 4.6 .1-.1 .3h-4.2l-2.5 2.5-.1 6.4a.45 .45 0 0 0 .1 .6 .45 .45 0 0 0 .6 0 .45 .45 0 0 0-.1-.7v-3.9h2.4l.3 .5 .5 .2v-.7h-3.2v-1.5h2.4l.2 .5-.2 .5h.8v-1.1l-3.2 .1v-.6l1-.9h1.4l.2 .4-.2 .5h.8l-.1-1-2.1 .1 1.3-1.3 .3 .1-.2 .6h.9l.3 .3 .1 4h.3a.54 .54 0 0 0 .5 .5 .54 .54 0 0 0 .5-.5l.4-.3a.5 .5 0 0 0 .5-.7l1.4-1.5 .7 .1-6.7 6.7h-8l-.6 .5h-2.3l-.1 .7-.2 .1a.48 .48 0 0 0-.5-.7 .48 .48 0 0 0-.3 .8l-.1 3-4.4 4.3-.1-14.6 4.8 .1a1.44 1.44 0 0 0 1.9 .6l.5-.3 .1-.5h-1v.8h-.5v-.8l-5.8 .1v-.6h7.3l-.1-.4-.6-.3h-.3v.7h-.5v-.7a.81 .81 0 0 0-1 .7h-4.8z"/>
<path d="M273.5 114.1l.5 .4v17.7l7.8 7.9 .1 3.4-.6 .7-.4-.4 .6-.6-.3-.2a1.85 1.85 0 0 0-1.9 .2l.6 .6-.4 .4-.6-.5a1.85 1.85 0 0 0 0 2.1l.6-.6 .4 .4-.5 .6a1.85 1.85 0 0 0 2.1 0l-.6-.6 .4-.4 .6 .7-.1 5.4a1.31 1.31 0 0 0-1.6-.7 .94 .94 0 0 0-.9-1.1 .94 .94 0 0 0-1 .9 .94 .94 0 0 0 .9 1 1.19 1.19 0 0 0-.8 1.5l-4.4 4.3h-4.6l-.1-.1 .3-.7h-2l.4 .7-.4 .1-.8-.8-.3-.8-.8-.1-.4 .3-.7-.1 .8-.9 .9 .2 .5-.4h1l.3 .5-.5 .8h2l-.5-.8 .2-1.1-.3-.3h-.8l-.4 .3h-1l-.4-.3h-.6l-.7 .5-.4-.7-.4-.2v.9l-.3 .4h-1v.3h-2.9l-.9-.9 4.6 .1v-.8l-.5 .2-.3 .5h-3.8l-1-1.1 .8-.1 .4-.7 .1-1.1h6.7l.3 .5 .5 .2v-.8l-7.5 .1v-1.3l6.6 .3 .1 .4h.9l.4 .3v1l.6-.1 .1 1.1h2.7l.3-.2v-4.9l-.3-.3h-2v-1.7l.4-.3 .2-.5h-1l-.3-.5 1.3-.1-.3-.5-.5-.1v.7h-.5v-.7h-.6v-1.3l-.2-.3h-3.7l-.2 .2v4.8l2.8 .2-3 .3-.2 2.2h-3.6v-3.4l-1-1.1 1.2-.1a.69 .69 0 0 0 .8 .7 .69 .69 0 0 0 .6-.9 .69 .69 0 0 0-.9-.4h-2.2v-.9h4.3a.51 .51 0 0 0 .6-.6 .51 .51 0 0 0-.7-.4 .5 .5 0 0 0-.4-.5 .5 .5 0 0 0-.6 .4h-3.1l-.1-.8 8.7-.1 4-4 .5-.1 .3 .3 .7 .1 .5-.4 .1-.9h-.6v1.3h-.5v-1.5l.3-.3h.8v-.6l-.4-.6 .1-4.8 .6-.3v-.7l.4-.4z"/>
<path d="M254.5 147.3h.2v1.2l.5 .4a.71 .71 0 0 0 1.1 .2l.6-.8 .7 .7v4.2l-.6 .3-2.6-2.5z"/>
<path d="M245.1 152l1.8-1.8h1.2l.7-.5 1 .8-.1 .7h-.3l-.1 1-.4-.1v-.9l-.8 .5-.4-.2a.5 .5 0 0 0-.5-.7 .5 .5 0 0 0-.3 .8l-.3 .9-.6-.2-.1 1.1-.4-.1v-1l-.4 .1z"/>
<path d="M256.6 145.6h1.4l.9 .9-.4 .1v2l.4 .1v3.1l-.5 .3-.2-.1v-3.1l-.2-.4v-1.9l-.5 .1z"/>
<path d="M198 93.3l.3 .1 .6-.5 .4 .3-.6 .6 .7 .3 1.1-.2 .1 1a1.25 1.25 0 0 0-1.9-.2 1.25 1.25 0 0 0 .1 1.9 1.25 1.25 0 0 0 1.8-.3l-.1 1.6a1.19 1.19 0 0 0-2 0 1.19 1.19 0 0 0 1 1.8 1.19 1.19 0 0 0 1.1-1.6l.8-.7 .4 .3-.6 .7a1.8 1.8 0 0 0 1.9-.1v1a1.35 1.35 0 0 0-2.2 .7 1.29 1.29 0 0 0 .8 1.2 1.29 1.29 0 0 0 1.4-.3v1.4a1.65 1.65 0 0 0-2.2 .1l-.3-.3a1.21 1.21 0 0 0-1.1-1.7 1.21 1.21 0 0 0-1.2 1.6 1.21 1.21 0 0 0 1.9 .7v.8a1.27 1.27 0 0 0-1.9 1.1 1.27 1.27 0 0 0 1.9 1.1v.8a1.25 1.25 0 0 0-1.9 1.2 1.25 1.25 0 0 0 1.9 1v.8a1.22 1.22 0 0 0-1.7 .5 1.22 1.22 0 0 0 .5 1.7 1.22 1.22 0 0 0 1.6-.5l.1 1-1.2 1.3v5.4l1.4 1.5 .1 .5-1.8 1.8v3.2l-4 4.1-.1 2a.71 .71 0 0 0-.2 1 .71 .71 0 0 0 1.1 0 .71 .71 0 0 0-.2-1v-1.8l4.1-4v.3l-2.4 2.5-.1 3a.7 .7 0 0 0-.1 1.1 .7 .7 0 0 0 1.1-.1 .7 .7 0 0 0-.4-1v-2.7l.9-.8 .1 5.5-1.1 1a.71 .71 0 0 0-.8 .7 .71 .71 0 0 0 .8 .7 .71 .71 0 0 0 .5-1l1.2-1.2v-5.9l1.7-1.8 .9-.2 .1-.9-.7-.3 .1-.6-.3-.5 .8-.3 .1-.7 .4-.3h.2l-.1 .9 .3 .3h.8l.5-.4 .4 .4h.7l.4-.3 .6 .6h.8l.6-.3 .1-.4h-.7v.7h-.5v-.8l.3-.4h.9l.1-.5h2.5l.3 .4-.7 .4 .1 3.5-.6-.5 .2-3-.2-.3-.8 .3v1.8l.4 1.6-.5 .3-1.4-.1 .6-.8-.8-.1-.4-.3v-.2h1.2l-.1-.4-.5-.3-.1 .7h-.5v-.7l-.5 .2-.3 .4-.5-.3h-.7l-.4 .4-.5-.4h-.7l-.4 .3v.7l.3 .3h.8l.5-.3 .4 .3 .5 .1 1.2 1.1h2.3a.6 .6 0 0 0 .9-.4l1.6 1.4h5.1v.7l3 2.9-.8 .1-.4-.5h-.7l-.4 .5h-.5l-.5-.5h-.6l-.5 .5h-.5l-.4-.5h-.6l-.4 .3-.1 1-.6-.6-.1-2.2h-.7l-.1 .8h-.3l-.1-.7-.7-.2-.1-.5-1.7-1.6-2-.1a.47 .47 0 0 0-.7 .3 .47 .47 0 0 0 .6 .5l-.6 .8v.6l-.7 .2-.1 .7h-.3l-.1-.8h-.5l-.3 .2-.1 .9h-1.2l-.5-.3h-.7l-.2 .2v.8l.3 .3h.7l.4-.4h1.1l.3 .5 .6 .1 .2-.8h.3l.1 .6 .7 .3v2.4l-.7 .3-.2 .7-.3-.8-.8 .1v1l-.3 .3v2.3l-1.2-.1-.3-.3v-.6l.4-.4-.1-.6-.2-.4 .4-.4 .2-.4h-1.3l-.2-.4 1.5-.1-.2-.5-.5-.3v.8h-.6l-.1-.9 1-.4v-.8l-.3-.3-.9 .2-.1 .7-.4 .5v2.3l.4 .6 .4 1.4-.4 .5 .2 1-.5 .8h2l-.5-.8 .2-.5 1-.1 .1 1.1-.3 .4v.7l.4 .3 .8-.1 .1-.9-.4-.4 .1-3 .5-.2 .1-.7 .4 .8 .7-.1 .2-1.9 .2 .2 .1 1.7 .6 .1 .3-.2v-1.8l-.9-.6v-2.2l.9-.2 .5 .4v-3.1a.27 .27 0 0 1 .1-.4 .27 .27 0 0 1 .3 .1l.4 .3-.3 .2v2.9l.5-.4 .8 .2v2.2l-.8 .6 .1 2-.4 .3-.1-.2 .1-2.1-.3-.3-.6 .3 .1 2.2-.6 .3-.1 .7 .1 .4 .6 .1a.52 .52 0 0 0 0 .7 .52 .52 0 0 0 .7 .1v-.8l1.4 .3 .5-.3 .2-.5h-.8v.8h-.5v-1l.3-.3h1l-.2-.6 .7-.2 .2-.7 .2 .1 .1 .7 .9-.1 .9 1.1h.7l.3-.3h.4l.3 .5 .4 .2v-.8h.5v.8l.8-.5 .4 .4 .9 .1 .6-.5 .1-.3h-.7v.8h-.6v-.8l-3.1 .1-.2-.9-1-.1-.7-.7-.1-1-.2-.3-.6 .1-.1 .7-.3 .1-.1-.7-.8-.3v-2.4l.8-.3 .2-.7 .2 .1 .2 .9 1.3 1.4 .1 .6 .3 .3 .8-.1 .2-.9-.3-.3-.6-.1-.4-.4 .1-.1 2-.1 .2 .3-.5 .3-.1 .5 4-.1-.5-.8 .2-.3 .7 .1 .6 .6v2.6l-1.5-.8 .5-.9-4 .1 .5 .7-.2 .3-1.8-.1-.2 .3 .2 .8 .8 .1 .4-.5h.5l.4 .5-.6 .9h4l-.5-.9 .2-.4h.2a.69 .69 0 0 0 1.2 .4v2.5l.3 .4a.46 .46 0 0 0 .5 .5 .46 .46 0 0 0 .4-.5 .46 .46 0 0 0-.4-.4l-.2-.2 .1-5.5 1 .9 .1 3.3 3.9 3.9h1.4l.7-.7 .2 .2-.9 .9h-13l-.1-.4h-1l-.3-.3v-.2h1.3l-.2-.4-.4-.3h-.2v.7h-.5v-.7l-.8 .4-1-.1-.5 .4-.7-.4h-.7l-.3 .3-.4-.5-.5-.1-.1 1-.4-.1v-.9l-.7 .5-1.1-.2-.3 .3 .1 .9 .8 .1 .4 .6-1.7 .1-1.3 1.4h-1.5l.1 2.4-.4-.1v-2.9l-10.3-.1v-1.9h9.5l.3 .5 .4 .2 .9-.1 .4-.5v-.2h-.7v.8h-.6v-.8l-10.2 .1 .1-14.3 .9-.6 5.5-.1 .2-.2z"/>
<path d="M205.6 143.3h9.1l.1 .3a.3 .3 0 0 1 .1 .4 .3 .3 0 0 1-.4 .1h-.7l-.4-.3-.4-.1v1.3l-.4 .2-.2-1.5-.4 .1-.4 .3-1.2-.4v1.4l-.3 .3h-1.1l-.4-.5h1.3v-1.2h-.8v1.2h-.5v-1.2l-.5 .1-.3 .3-1.2-.4v1.3l-.4 .2-.1-1.5h-.5z"/>
<path d="M246.6 140.2l3.8 3.7-2.2 .1-1.1 1.1-1.4-.3 .1-.2h1.1v-.2a.58 .58 0 0 0 .6-.7 .58 .58 0 0 0-.9-.4v-.6a.52 .52 0 0 0 .8-.4 .52 .52 0 0 0-.8-.4z"/>
<path d="M213.6 118h.6l-.1 2.3 .5 .1 1.6 1.6h2l.3 .4h.7l.4-.3v-.7h.5v.7l.3 .3h.7l.3-.4h.6l.4 .4 1.1-.2 .4 .4 1 .1 .5-.3 .2-.4h-.8v.7h-.5v-1.2l1.3-.1-.2-.4-.5-.3-.1 .8h-.5v-.8l-.8 .5-1.1-.1-.4 .3h-.6l-.4-.3h-.6l-.3 .3h-.5l-.4-.3h-.7l-.3 .3h-1.8l-.8-.9 .6-.3v-2.2h.5l-.1 2.1 .2 .3 .7-.1 .1-.8h.6l.4 .3h.7l.3-.3-.2-.9-.8-.1-.4 .4-.6-.1-.1-.8h6.5l.1 .2-.7 .5-1-.2-.4 .4h-.5l-.4-.4h-.7l-.3 .3v.7l.4 .3h.6l.4-.3h.5l.4 .3 1.1-.1 .8 .5v-1h.3l.2 1 .8-.3 .1 .5 1.2 1.1 4 .1v.2l-3.4 3.3-.1 1-2.6 2.5-.6 .1-.3 .3 .2 .9h1l.2-.8 2.7-2.7 .5 .5-.1 1.4-.9 .3-.2 .9-.3 .2-.1-.1a.59 .59 0 0 0 .1-.8 .59 .59 0 0 0-.8-.1 .59 .59 0 0 0-.2 .8v1.3a.66 .66 0 0 0 .1 .8 .66 .66 0 0 0 .8 .1l.4 1.7 .4 .3 .9-.2v-.8l-.2-.4h-.7l-.2-.5 1.4 .1a.49 .49 0 0 0 .5 .1 .49 .49 0 0 0 .3-.4l.9-.8 .1-1.4 .2 .1 .1 1.4 .6 .2 .3-.3-.1-1.9-.7-.1-.5-.5h-1l.1-.3h.4a.43 .43 0 0 0 .6-.6 .43 .43 0 0 0-.8-.1h-.2l-.2-.3 .5-.8h-.9l-.4-.5h5v-.8l-.7 .3-.7-.3v.8h-.5v-.8l-.5 .1-.2 .6h-1.1l-.3-.6-.4-.1v.8h-.6v-1l2.3-2.3h3.6l.2 2.5h-.6v1l-.4 .3h-2.7l.4 .7-.1 1.2 .3 .3h.6l.1 .3-.2 2.2-1.1 1.1v1.7l-.7-.3v1.4l-.4 .3h-.7l-.1 .7-.6-.5-.1-1.1h-1l-.1 1.1 1.5 1.2-2 .2a.59 .59 0 0 0 0-.9 .59 .59 0 0 0-.8 0 .59 .59 0 0 0-.1 .8v3.5l-.2 .8-3.6-3.5v-3.1l-.2-.3h7.3v.6h.6v-1.2l-.6 .6h-7.3l-3.4-3.5 .1-.9h-1l-.6-.9 .8-.1v.5h1l.3 .3v.9l.4-.1 .4-.5 .5 .3h.6l.4-.4 .5 .1 .4 .3h.7l.3-.3-.1-.9-.9-.1-.4 .3h-.5l-.4-.3h-.6l-.7-.7-2.8-.1 .8-.8h.4l.3 .3h.9l.2-.9h.5v.7l.3 .2h.7l.3-.3h.6l.4 .3 1.1-.1 .6 .5 1-.1 .5-.7h-.8v.8h-.5v-1.3h1.3l-.2-.4-.4-.3h-.2v.7h-.5v-.7l-.8 .5-1.1-.2-.4 .4h-.6l-.4-.4-.6 .1-.3 .3h-.5l-.4-.4-.7 .1-.4 .3-.7-.7 .4-.5v-.9h-.7l-.1-.3 1-.3 .4 1 .8 .1 .4-.3v-.6h.5v.6l.3 .3 1.6-.3 .4 .3 1.1-.1 .4 .4 1 .1 .5-.3 .2-.4h-.8v.7h-.5v-1.2h1.3l-.3-.6-.5-.2v.8h-.5v-.8l-.9 .5-1-.1-.4 .3h-.5l-.4-.4h-.6l-.4 .4h-.5l-.3-.4h-.6l-1.2-1.2h-3.5l-1.2 .9v1.8l.6 .2a.52 .52 0 0 0 .4 .6 .52 .52 0 0 0 .6-.3l.6-.5-.1-2h.4v2l.8 .7-.5 .5-1-.2-.5 .4h-.5l-.3-.3h-.8l-.3 .2 .1 .9 .9 .1 .4-.3h.5l.5 .3 1-.1 .6 .7h-4.7l-.4-.3 .6-.6-.1-.8-.6-.3 .2-2.6 .3 .1v1.7l.6 .1 .3-.2v-1.8l-1.5-1.4 1-.2 1.3-1.3 .5-.1z"/>
<path d="M269.4 110.3l.9-.4 .1 .1v14.3l-.5 .5a.6 .6 0 0 0-.5 .4 .6 .6 0 0 0 .2 .6 .45 .45 0 0 0 .2 .7 .45 .45 0 0 0 .6-.5l1-1.1 .2-15 .8 .5v16.7l-1.6 1.6-.8 .1-.8-.4-.1 .9h-.4v-.9l-.8 .4h-1.2l-.2 .9 .5 .4v.5a.53 .53 0 0 0 .1 .6 .53 .53 0 0 0 .6 .1l.1 4h-2.2l.4 .8v1.2l.9 .9 .4 .1a.47 .47 0 0 0 .5 .1 .47 .47 0 0 0 .3-.5l.6-.6v-1.5l.3-.1 .1 1.8-2.9 2.9-4.7 .1 1.8-2.1 .1-.4 .9-.1 .6-.4v-.3h-.7v.7h-.5v-1.2l1.2-.1-.3-.5-.4-.1v.7h-.5v-.7h-.3l-.1-.6 .7-.2 .2-.5 3.4 .1-.2-.5-.5-.3-.1 .8h-.5v-.8l-.4 .2-.3 .5-1.4-.1a.74 .74 0 0 0-.9-.6 .74 .74 0 0 0-.5 1l-.1 1.3h-1.1v-1l2.3-2.3 .1-.4 1.1 .2 .5-.6v-.6h-.5v1.2h-.5v-1.4l.3-.3 .7-.1v-.6l-.3-.6v-4.1l1.3-1v-.7l1.5-1.6v-9.7l1.3-1.3z"/>
<path d="M249.4 132.1l.4 .2-.1 4.8h.6v.3l-.8 .8a.49 .49 0 0 0-.5 .6 .49 .49 0 0 0 .7 .4l.3 .2 .4-.1 1-1.2v-1.2l.3-.1v3.6h-2.3l-1.5-1.5v-1l1.1-.3 .4-.5v-3.5l-.4-.4 .3-.5z"/>
<path d="M242 124.8h.3l.3 .6h1.4l.2-.3-.1-.6-.9-.1-.1-.3h2.9v.2l-.9 1-.7 .1-.2 .6h-.7v.5h1l.1-.2h1.3v-1l.6-.6 .3-.1 .4 .5 .7 .1 .9-.6 .2 .7-1.1 1.1-.9 .2v.8l.3 .7-.8 .9a.76 .76 0 0 0-1.2-.6h-2.5a.57 .57 0 0 0-.8 .1 .57 .57 0 0 0 .1 .8 .57 .57 0 0 0 .7 0h2.5l.6 .2-1.7 1.7-.4-.3h-1.3l-.4 .6h-.6v1.7l-1.9 1.9-.1 4.8-1.1-1.1v-5.3l.4-.1v-.8h.5v.8l.8-.5 .9 .2v-.5h-2.2v-.5h2.2v-.6l-1 .3-.7-.4v.7h-.5v-.7h-.3l-.1-.3 1-.1 .4-.3 2.1 .2 .3-.7-.3-.3-2.1 .1-.4-.3-.8-.1 1.1-1.2 1.6-.1 .3-.5a.59 .59 0 0 1 1-.2 1.63 1.63 0 0 0 1.9-.4v-.2h-1v.6h-.5v-1.6h-.6l-.5 .6-.2-.1z"/>
<path d="M241.9 135.1a.57 .57 0 0 0 .6 .3 .57 .57 0 0 0 .4-.5l2.2-2.2h.8l.1 .4-.1 .6h.8v-1.1l-1.6 .1 .6-.6h1.2l.3 .4-.1 1.3-.3 .3-.9 .1 .1 .5-.5 .2-.1 .8 .3 .4h.8l.3-.3v-.7h.4l.1 3.8h-.5l.1-.5h-1.2v-.3l1.2-.1-.4-.5-1-.1-.5-.5a.64 .64 0 0 0-1-.1l-.1-.4 .2-.3h.7l.2-.3v-.7l-.2-.3-1.1 .1-.6 2 .1 .9-.3 .1-.8-.4v.9l-.5 .1v-1l-.3-.1v-1.6z"/>
<path d="M261.6 130.6l.3 .1 .2 2.6-1.6 1.6-.1 .9-.8-.3v1.9l.8-.3v1.3h-4.1l.1-.3h1.9l-.4-.6-.5-.1v-.3l.9-.1 .8 .4v-1.6l.7-1.1v-1.4l.7-.1 .6-.7 .4-.2z"/>
<path d="M235.5 122.8h.8l1.3 1.2 2.5 .2-.3 .4h-.7l-.3 .3v.7l.4 .4-.5 .4-.2 .5 1 .1-.1 .4h-.9l.6 .8-1.4 1.5h-.9l-.2 .3v.7l.3 .4v.6l-.4 .4 .1 .6 .3 .4v.8l-1.9 1.9-.5 .1-.1-1.1 1-1z"/>
<path d="M258.7 117.7l.5 .2 .2 .8 .7 .1 .4-.3v-.7l-.3-.3h-.6l-.1-.4h1.4l.5 .2 .7-.2 1.9 .1-.1 .6-3.1 3.1-.7 .1v.7l-2.2 2.2v8.1l.7 .9h-.6v.8h.8v-.6l.4 .4v1l-.6 .5-.1-.2 .3-.6-1-.1-.3-.3v-.9l-.3-.1v-10.9l.5-.5 .7-.1 .4-.3 .3 .5 .5 .2v-1.3h1.3l-.2-.4-.4-.3-.2 .7h-.5v-.7l-.5 .2-.3 .4-.4-.3-.1-1.1 .4-.4z"/>
<path d="M252.8 117.7h4.5l.1 .8 .3 .4v1.1l-.3 .3v.5l-.8 .8v1.2l-.7 .1-2.2 2.4h-1.1l-.3 .6h-.6v.6l2.3-.2 .2-.7 1.9-1.9h.5v8.6l-.5 .2-.7 .9-.2 .9a.55 .55 0 0 0-.8-.2 .55 .55 0 0 0-.1 .8l-.9-.1v-1.2l.4-.4h1.1l.7-.8v-1l-.7-1.3 .5-.4-.1-.9h-1.3l-.7-.4 .1 2.4h-.4l-.2-.4v-2l-.6 .1-.3 .5h-.3v.9l-.3 .3h-1l.5 .8v1.3l.3 .1 1.2-.1-.2 2.6-.2-.1v-1.3a.46 .46 0 0 0 0-.7 .46 .46 0 0 0-.6 0 .46 .46 0 0 0 0 .7v1.3l-.9 .1-.1-2.9-.9-.9-1.9-.2 1-1.1 2.6-.1v-.7l-.5 .1-.3 .5h-.3l.1-.3-.3-.5 1-.5a.47 .47 0 0 0 .4-.8 1.04 1.04 0 0 0 1.5-.5h-1v.5h-.5v-1.6h-.4l-.6 .3-.5-.1v.9h-.4l-.1-1.1 .8-.9 .2-1 .6 .2-.3 .4 .1 .7h1.6l.1-.8-.5-.2-.6-.8 1.9-.1 1.9-1.8a1.01 1.01 0 0 0 1.3-.9 1.01 1.01 0 0 0-1.3-1 1.01 1.01 0 0 0-.5 1.5l-1.7 1.6-3.2-.1 3-3z"/>
<path d="M254.6 131.7h.4v.4l-.4 .1z"/>
<path d="M251.9 131l.3-.1 .1 .7a.31 .31 0 0 1-.4-.1 .31 .31 0 0 1 0-.3z"/>
<path d="M259.2 127.7l.3-.3h1.2l-.1 2.9-1.1-.1-.3-.3v-.2h1.2l-.4-.7h-.3v.7h-.5v-.7l-.7 .1 .1-.6 1.2 .2 .6-.4v-.4h-.7v.8h-.5z"/>
<path d="M267.7 100.5l.6-.1a1.37 1.37 0 0 0 2.1 .6l-.1 1.2a1.23 1.23 0 0 0-1.7 .2 1.23 1.23 0 0 0 .1 1.7 1.23 1.23 0 0 0 1.7-.1l-.1 1.2a1.23 1.23 0 0 0-1.7 .2 1.23 1.23 0 0 0 .1 1.7 1.23 1.23 0 0 0 1.7-.1l-.1 1.2a1.22 1.22 0 0 0-1.8 .2 1.22 1.22 0 0 0 .3 1.7v1.1l-1.3 1.2-.1-.7a1.22 1.22 0 0 0 .4-1.9 1.22 1.22 0 0 0-2 .3 1.22 1.22 0 0 0 1 1.7v9.4l-2.4 2.4-.9 .2-.2 1.4-.7-.3v1.4h-.4l-.1-1.4-.6 .3-.6-1 4-4.1a.74 .74 0 0 0 .8-.4 .74 .74 0 0 0-.2-.9v-11.3h.3a1.18 1.18 0 0 0 1.6 1.2 1.18 1.18 0 0 0 .3-2 1.18 1.18 0 0 0-1.9 .7l-.3 .1v-3h.3a1.18 1.18 0 0 0 1.6 1.2 1.18 1.18 0 0 0 .3-2 1.18 1.18 0 0 0-1.9 .7l-.3 .1v-.9l.9-.9a1.31 1.31 0 0 0 1.6-.6 1.31 1.31 0 0 0-.3-1.6z"/>
<path d="M236.7 121.6h.8l.1 .3h1l.3 .3v.9l.4-.1 .5-.7 .9 1-2.9 .1-1-1h.8l.3 .6 .5 .1v-.7h-1.6z"/>
<path d="M247.1 120.5l.3-.3h1.1l.4-.3 .2 .3-.3 .6h-.7v.6h1l.1-.2 .8 .1-.8 .8-.1-.2h-1v.6h.7l-.5 .5-.5-.3-1 .2-.1-.2 .3-.3 .6 .1v-1.7h-.5z"/>
<path d="M239.3 107.7l4.8-.2 .1 .3h1.2l.3 .3v.8a.79 .79 0 0 0 1-.6l.9 .1 1.1 1.1-.2 .5 .2 .9h.9l.2-.2v-.8l-.9-1.1 .9-.1 .4-.7h-.8v.7h-.5v-.8l.4-.4h.9v-.6h4.1l.7-.5 1.4-.2-.1 2.5-5.6 5.6h-.7v.8l.5-.1-.1 1.2-1-1v-1.4h1.3l-.3-.5-.4-.2v.7h-.6v-.7l-.4 .2-.4 .4-.4-.3-1.3 .1-1.1-1a.45 .45 0 0 0-.6-.3 .45 .45 0 0 0-.2 .6 .45 .45 0 0 0 .5 .3l.3 .5-.7 .1-.4 .5h1.2l.3 .3v.7h.6l.5-.6 .8 .2 1.2 1.1-.3 .5 .2 .8 .7 .1 .5 .4h1.5l.1 1.6-1.3 1.3-.6-.4-1.5-1.5-1.5-.1-.7-.8a.46 .46 0 0 0-.8-.1 .46 .46 0 0 0 .3 .7v.8l1.1 .1-.2 .7-.2-.3h-.7v.7h.5v1l-.7-.3-.6-.5 .3-.2v-2l-.5 .2-.3 .5-.4-.3h-.7l-2.1-2.2 .5-.1 .2-.4h2.9l.2 .7 1.9 .1 .4 .4h.7l.3-.3v-.9l-.9-.1-.6 .3-.5-.5h-1.3l-.2 .3h-2.9l.5-.4 2.1 .1 .3-.6h.7v-.5l-3.3 .4-1.1 .6v-5.7l-.2-.2h3.4l.2 .6 1.9-.1 .5 .6 .9-.1v-1l-2-.3h-1.3l-.2 .3h-3.4l-.2-.3 .4-.2 2.9 .2 .3-.7 .7 .1v-.6l-2.6 .4-1.7-.1-.5 .4z"/>
<path d="M202.9 118.8h1l.3-.3 .6 .3h.7l.4-.3 .4 .5 .5 .1v-.9h.4l.1 .9 .7-.4 .4 .2 .5 .5 .1 .9 .6 .1 .3-.3-.1-2.1h.4v2.2l.7 .2 .3-.3-.2-2.1h.5v2.2l.7 .3-.7 .7h-3.4l-.1-.2-.9-.1-.3-.3v-.2h1.2l-.1-.4-.5-.3-.1 .7h-.5v-.7l-.5 .2-.3 .4-.5-.3-.7 .1-.4 .3-.5-.3h-1z"/>
<path d="M213.7 85.9l2.6-.2 1.8 1.8 .1 .9 2.3-.1v.6l-2.1-.2-.3 .3 .3 .7 1.6 .1-1.8 .3v.7l.7 .2 .3 .3a.5 .5 0 0 0 .7 .4 .5 .5 0 0 0 .2-.7l.4-.1v2l-.6-.1v2h.6v1h-.3v2l.3 .1v1h-.6v2l.6-.1v1.3l-.5 .6-.9 .2v.9l1 .5h1.7l-.3 .7h1.4l.3 .3v.8l-3 3.1-.3-.9h-1.2v2.4l1.3 .1v-.9l.4-.1 1.4-1.4h1.9v2.3l1.3 .1v-2.5l-3.2 .1 3.6-3.6 1.3 .1 .3 .8h2.2l.1 .7h.7l.1 .3-.8 .2-.1 .5a.53 .53 0 0 0-.9 .2 .53 .53 0 0 0 .5 .7v2.4l.9 .1 .9 .8 5.1-.2 .2-1 2.1-1.8 1.5 1.5v.6l.3 .5v6l-.5-.3v-.7l-.4-.2h-.8l-.1 .9-.6 .5h-.3v-.4h-2v.4l-1.6 1.6h-.7l-.3 .4 .2 .9h.9l.2-.3 .1-.6 1.5-1.3 .1 1-.7 .8-.3 1.1-4.1-.1-.1-.4 .4-.3 1.2 .1 .1-1-.3-.3h-2v.5l.6 .1-.4 .5-1.3 .1-.2 .7-1.2 .1-.9-.9-.1-1.3-1.1-1.3h.5l1.5 1.5-.5 .4 .3 .8h1.3l.3-.7h.7v-.5h-1l-.3 .2-.5-.7h3.3l-.1-.2-.3-.3-.6-.1v.6h-.5v-.6h-.4l-.6 .6h-.8l-1.5-1.6-.8-.1v-2.3h1.2l.1 2.4 1.2-.1v-2.3h1.2v2.3l1.2 .1 .2-.2-.1-2.3-1.3 .1-5-.1-.1 2.4h-3.6l-.1-.7 1.6-.1 5.2-5.2h.3l4.2 4.2 .2 1.9h1.1l.1-.5 4.4 .1-.2-.5-.5-.3-.1 .8h-.5v-.8l-.4 .2-.3 .5h-2.4v-1.9l-1.1-.4h2.4v.2a1.65 1.65 0 0 0 1.9 .2l.3-.8h-.9v.9h-.5v-.9h-.8v.4h-2.4l-1.3-1.3h3.7v.4h2.2v-.4l-.3-.4h-.6v.8h-.5v-.8h-.6l-.2 .4h-3.7l-2.6-2.7-.1-1.8-1.2-.1-.2 1.9-5 5.1h-1.1l-.3-.9-1 .1-.3 .8-2.5-.1 .2-.4-.1-.9 .2-.5-.2-.9 .2-2.1-.3-.4h-.9v-.8l1.1-.2 .5-.5-.8-.1v.7h-.5v-1.3h1.3l-.3-.5-.5-.2v.7h-.5v-.7l-.3-.1v-3.7h2.1l.3 .9-.3 1.6 .3 .4 1.2-.1 .6 .4h.8l.5-.2 .1-.5h-.8v.7h-.5v-.9h2.1l.6 .5h.6v-.5h-3.3v-1h.5v.7h.8l-.1-.4-.5-.4-1 .1-.4 .5-.5-.2-.1-.7 .5-.4v-.6l-.3-.3h-.8l-.3 .4h-2.1v-1.7l-.9-.8 .7-.3 .1-.8h.5v.6l.3 .3h.8l.5-.3 .5 .3 1.1-.1 .7 .5v-2l-.7 .5-1.1-.2-.5 .4-.5-.4h-.7l-.4 .4h-.5l-.3-.4h-.6l-1.6-1.6v-1.8l1.1 .9 .1 .5 .3 .3 .8-.1 .2-.8h.5v.6l.3 .3h.8l.3-.4h.5l.5 .4 1-.2 .7 .5 .1-2-.8 .5-1-.1-.4 .3h-.6l-.3-.3h-.7l-.4 .4h-.5l-.3-.4-.7-.1-.7-.6v-4.2h1.9l.5-.3 .1-.3h-1.2v.6h-.5v-.7l.3-.4h1.4l-.4-.5 .1-.8 .6-.4 .1 4.6-.6 .2-.2 1.1-.4-.4-.2-.8-.8-.1-.3 .3 .1 .9 .8 .1 .7 .7h1.7l.7-.7 .9-.1 .8 .5v-2l-.7 .5-1.3-.1-.2 .9-.3 .1-.1-6.4-1.5-1.6h-1.5z"/>
<path d="M211.6 116.4h1l.2-.3 1 1.2h-1.2v-.4h-1z"/>
<path d="M259.3 103.6h.9l.4-.4 .9 .2 .6-.5 .4 .4v1.3a.54 .54 0 0 0 0 .7 .54 .54 0 0 0 .7 .1v4.7l.8 .9v5.1l-1.9 .1-.7-.2-.5 .2h-2.7l-.6-.5 .1-.9-.9 .1-.6-.6h1.5v-.7l-.5 .1-.3 .6h-.7l-.2-.2a1.02 1.02 0 0 0-.1-1.8 1.02 1.02 0 0 0-1.5 .9l.6 1.2 2.5 2.6h-6.3l-.1-2.2 5.8-5.8 .2-.5 .4 1 1.1 .1v1.3l-.5 .5-.8 .1v.8l.3 .4h.7l.3-.3v-.6l.5-.3 .4 2.3-.5 .4-.3-.5-.5-.1v2l.9-.6a.81 .81 0 0 0 .8 .8l.2-.1a.48 .48 0 0 1 .2-.6 .48 .48 0 0 1 .6 .2l.5-.4-.1-4.1-1-1.1 .2-1-.3-.5v-1.5l.3-.4v-.7l-.3-.3-.9-.1z"/>
<path d="M208.7 107.8l4.5 .1 .1 .6 .4 .3v1l-.5 .4v.7l.3 .3h1l-.1 .8-.3 .1v2h.3v.6l-.7-.5-.1-.9h-.8l-.5-.5h1.3v-.7l-.5 .2-.3 .5h-.5l-.7-.7-.1-1.8-1.6-1.6-1.5-.1z"/>
<path d="M232.5 105.7h1.1l.6-.5h1.4v.3h-1.5v.9l-.4 .6h1.4l.3 .3v.7h.8l.6-.6 .5 .5-1.7 1.9-1.3 .1-.1 1.1-1.6-.1 .1-2.5-.4-.2v-.6l1.4-.1 .4 .5h.8v-.5h-2.6z"/>
<path d="M198.4 70l.9-.4 21.8 .1-.5 .6-.8 .2v1.1l-.2 .2a.53 .53 0 0 0-.5-.3 .53 .53 0 0 0-.5 .5l-3.7 3.4a.49 .49 0 0 0-.2-.5 .49 .49 0 0 0-.6 0l-2.5-.1-.1 .6 .2 .3 2.4-.2 .6 .3-.7 .8-.5-.6h-1.8l-.2 .6a.66 .66 0 0 0-.6 .4 .66 .66 0 0 0 .1 .7h.5v.3l-.6 .1-2.3-2.1h-1.8l-.2 .3 .2 .7 2.1-.1 .3 .3-.3 .2-2.1-.1-.2 .3 .1 .6h2.5l.6-.4 .9 .9h.8l.1 .8 1.8 .1-.1 .2-1.7 .1-.1 1.4-2.9-2.7h-1.9l-.1 .9-.4 .6h3.1l2.2 2.2 1.7 .2-.1 .5-1.2 1.3v13.5l1.7 1.8 .1 .3-5-4.6a1.21 1.21 0 0 0-1.8-.7 1.21 1.21 0 0 0-.1 1.9 1.21 1.21 0 0 0 1.9-.4l2.1 2-2.1 .2a1.22 1.22 0 0 0-1.9-.6 1.22 1.22 0 0 0 .1 2 1.22 1.22 0 0 0 1.8-.8h2.1l1.7 1.7 .1 .6-3.8 .1a1.19 1.19 0 0 0-1.6-1 1.19 1.19 0 0 0-.6 1.9 1.19 1.19 0 0 0 1.9 0l.2-.2h4.7a.47 .47 0 0 0 .8-.3l.3 .1-.1 5.5-5.7-.1a1.25 1.25 0 0 0-1.9-.5 1.25 1.25 0 0 0-.1 1.9h-.6l-.6-.6v-.8a1.26 1.26 0 0 0 .7-1.2 1.26 1.26 0 0 0-.7-1.1v-.4h.9a1.23 1.23 0 0 0 .9 1.2 1.23 1.23 0 0 0 1.4-.7h2.6l1.5 1.4a.46 .46 0 0 0 .4 .5 .46 .46 0 0 0 .5-.4 .46 .46 0 0 0-.5-.5l-1.6-1.6h-2.8a1.24 1.24 0 0 0-1.3-1 1.24 1.24 0 0 0-1.1 1.1h-.9v-.2a1.3 1.3 0 0 0 .7-1.2 1.3 1.3 0 0 0-.7-1.2v-.7a1.25 1.25 0 0 0 .4-1.9 1.25 1.25 0 0 0-1.9-.1v-1.2a1.24 1.24 0 0 0 2-.2 1.24 1.24 0 0 0-.7-1.9l-1.2 .3-.9-1.1 .3-1.1h.4a1.18 1.18 0 0 0 1.6 1.2 1.18 1.18 0 0 0 .3-2 1.18 1.18 0 0 0-1.9 .7l-.4 .1-.2-.8-.6 .6-.4-.4 .6-.6-.3-.3h3.8a1.18 1.18 0 0 0 1.6 1.2 1.18 1.18 0 0 0 .3-2 1.18 1.18 0 0 0-1.9 .7l-3.8 .1 .3-.2-.6-.6 .4-.3 .6 .5 .2-.9h.4v.2a1.18 1.18 0 0 0 1.8 .9 1.18 1.18 0 0 0 0-2 1.18 1.18 0 0 0-1.8 .9h-.4l-.2-.8-.6 .6-.4-.4 .6-.6-.3-.3h3.8v.2a1.18 1.18 0 0 0 1.8 .9 1.18 1.18 0 0 0 0-2 1.18 1.18 0 0 0-1.8 .9h-3.8l.3-.2-.6-.6 .4-.3 .6 .5 .2-.9h.4a1.18 1.18 0 0 0 1.6 1.2 1.18 1.18 0 0 0 .3-2 1.18 1.18 0 0 0-1.9 .6l-.4 .2-.2-.8-.6 .6-.4-.4 .6-.6-.7-.2-1 .2 .6 .6-.4 .4-.8-.7 .1-.6h5.7a1.18 1.18 0 0 0 1.6 1.2 1.18 1.18 0 0 0 .3-2 1.18 1.18 0 0 0-1.9 .7l-5.7 .1a1.2 1.2 0 0 0-1.7-.9 1.2 1.2 0 0 0-.3 1.9 1.2 1.2 0 0 0 1.9-.2v1.6a1.25 1.25 0 0 0-1.9-.2 1.25 1.25 0 0 0 .1 1.9 1.25 1.25 0 0 0 1.8-.3l-.1 1-1.1-.2-.7 .2 .6 .6-.4 .4-.6-.6-.3 .1v-11.2h8.2l.6 .5h1.8l.6-.5h-1.2v.5h-.5v-.5h-9.5v-5.6h8.6l.2 .7h1.8l.3-.2v-.5l-.3-.2h-1.8l-.2 .2h-8.6v-1.2h8.6v.4l.2 .2h1.8l.3-.6h2.6l.2 .6 2.5-.1a.45 .45 0 0 0 .6-.1 .45 .45 0 0 0 0-.6 .45 .45 0 0 0-.7 .1l-2.3-.2-.3 .3h-2.6l-.3-.3h-1.8l-.2 .3h-8.6v-1.3h8.6v.4l.2 .3h1.8l.3-.7h2.6l.2 .7h1.8l.3-.3v-.4l-.5-.4 .5-.4 .4 .1v.5l.3 .3 1.1-.1 .6 .4 1.1-.1 .4-.6h-.8v.7h-.5v-1.2h1.3l-.2-.5-.6-.3v.8h-.5v-.8l-.9 .5-2.1-.4-1.1 1.2h-.6l-.2 .3h-2.6l-.3-.3h-1.8l-.2 .3h-8.6v-1.8z"/>
<path d="M257.5 103.6h1.1v1.3l-.3 .1v1.9l.3 .1v1.3h-.8l-.3-.4v-.9l.3-.1v-1.9l-.3-.1z"/>
<path d="M232.6 102.5h.3a.57 .57 0 0 0 .7 0 .57 .57 0 0 0 .2-.6l.4 .7h1.9l.3-.3 1.6 1.4 1.2 .2 2.1-.1 .4 .6-2.5-.2-.3 .3 .1 .5 2 .2 .8-.2 .5 .6-1 .1-.3-.2h-1.8l-.3 .2a.55 .55 0 0 0-.7-.1 .55 .55 0 0 0-.2 .6l-.2 .3-1.5-1.5-.2-.8h-1.9l-.9 .9h-.5v-.5l-.8-.1v-.4h.8l-.2-.9h1.4v.5l.3 .2h1.7l.3-.2v-.5l-.3-.3-3.4 .3-.3-.3z"/>
<path d="M227.3 87.6l.5 .4v.7l.2 .2 2.3-.1 1.1 1.1 .5 1.7 1.3 1.2h3.7l1.4-1.3v-.6l.4-.4v-.6l-.3-.3-1 .1v.9l.3 .6-.9 1-1.9-.1 .9-1.2h.8l.2-.3v-3.1l.4-.1 .2-.4h2.1a.71 .71 0 0 0 1.1 .2 .71 .71 0 0 0 0-1.1 .71 .71 0 0 0-1.1 .3h-2.1l-.3-.5h-1.4v1.4l.5 .3v1.8l-.6 .3-.1 .7-.4 .4-.1-.3h-.8l.1 .8-.2 .9h-.7l-.9-.9v-.3l.4-.3 .8 .5v-1.2h1.3l-.2-.5-.6-.3v.8h-.5v-.8l-.8 .5-.9-.1-1.1-1.1 1.4-1.5h.5l.2 .4h1.4v-1.5h-1.3l-.3 .4-.7 .1-1.8 1.7-.3-.1 .4-.6-1.5-.1 .1-.4h1.4l-.4-.5v-.8l.7-.7h2.3l.5-.4 .8 .8h1.7l1.1-1 .9-.1 .3-1.1 .3 .1v.8l.6 .7a.48 .48 0 0 0 .8 .2 .48 .48 0 0 0-.2-.8l.1-.9 .2-.1 .3 .3 .2 .8 1 .1v3.7l2 2 .2 .6 .7 .2-.1 .2-.7 .1v.7l.7 .2 .1 .5 .7 .9h.7v.7l-.8 .4-.7-.4-1 .2-.8-.5v2l.8-.5 1.1 .1 .4-.3 .6 .3 1 .1v1.3l-1.4 .8-.7-.4-1 .1-.8-.4v1.9l.8-.4 1.1 .1 .4-.4 .6 .4 .8-.1 .2-.9 .5-.5 .1-1.6 .8 .1 .5 .4h2.1l.5-.5h.7l.2-.3h5.1l.3 .5 .5 .2v-.8l-5.9 .1v-.6l.3-.2h4.7l.1 .2h.9l.3 .3 .1 1 .5-.2 .3-.5 1.1 .5-.9 .9h-8.9l-.7 .6-.7 .1-.3 .4-.6-.4-.9 .1-.1 1 .9 .2 .6-.4 .4 .4h.7l.4-.3 .6 .6h.9l.5-.3 .1-.4h-.7v.7h-.5v-.9l.3-.3h.9l.1-.5h7.2l2.9-2.8h3.9v.3a1.35 1.35 0 0 0 0 2.1l-3.9 .1-1.4 1.2-.4-.5-.5-.1-.1 1.4-.4-.1v-1.3l-.5 .1-.3 .5-.5-.3h-.6l-.4 .3-.6-.3h-.8l-.2 .3v.7l.5 .4a.53 .53 0 0 0-.2 .8 .53 .53 0 0 0 .8 .1l-.1 1.5-.9-.9-1-.4v-1.1l.3-.5v-.7l-.3-.2-.9 .2-.1 .7 .4 .5v1.1l-.2 .1-.7-.4v2l.7-.5 .8 .2-.1 .2 .5 .6-.3 .4-.6-.6-.2 .6 .1 .6 .1 .2 .6-.5 .3 .3-.5 .6 .4 .2 1.2-.2v.8a1.13 1.13 0 0 0-1.2-.2 1.13 1.13 0 0 0-.7 1l.1 .3-.4 .4h-3.1l-.1-3a.46 .46 0 0 0 0-.7 .46 .46 0 0 0-.7 0 .46 .46 0 0 0 .1 .7v2.3l-.2 .7-1.7-.1 .5-.6h.7l.2-.3v-.7l-.4-.4v-.6l.5-.4-.1-.6-.2-.3h-.8l-.3 .3-.4-.5-.5-.2v2l.5-.2 .3-.4 .3 .3-.2 1.6-.4 .4-.1-1-.2-.3h-.8l-.4 .3-1.9-.2-.3 .5-.4-.1-.7 .1-.3-.3 .1-.2h1.2l.2-.6h.7v-.6h.5v.6l.8-.2 .6 .3v-.7h-2.9l-.3 .3-.6-.8h1.9v-.5h.5v.5h1.4v-.8l-.6 .4-.4-.1a1.4 1.4 0 0 0-1.9 .5h-.9l-.4-.2-.5 .3-.2-1.2-.4-.4h10.2l.2 .5 .6 .2v-.8l-11 .1-.8-.8h-1.8l-.2-.3h2l.4-.8 .2 .2 .2 .9h1.2l.6 .4 .8 .1 .5-.3h7.9v-.7l-.6 .2-.2 .5h-7.1l.2-.5h-.8v.8h-.5v-1.3h1.3l-.4-.6-.4-.1v.7h-.5v-.7l-.8 .4-.8-.1-.2-.2 .1-.9h-.8v.3l-.6 .2-.6 .5-1.1 .1-.1-1.6h3.2v-.7l-.5 .1-.3 .6h-2.4l-.1-1.6a.83 .83 0 0 0-1-.9h3.5l.3 .5 .5 .2v-.8l-4.3 .1-.6-.6h4.9v-.7l-.5 .2-.3 .5h-6.6l-.4-.3-.6-.1-3.4-3.4-.5-.2h-1.6l.1-.3 1.6-.1v-.8l-1.9-.1-.3 .7-.9 .7-.1-2.1z"/>
<path d="M221.2 88.1l.3 .2 .1 .6a.48 .48 0 0 0 .5 .5 .48 .48 0 0 0 .5-.5 .48 .48 0 0 0-.4-.5l.2-.3 .7 .8 1.7 .1-.1 .2-1.8 .2v.7l1.9 .2-.1 .2-1.8 .1v.8l2 .1 1.1-1.4 .1 .5a.56 .56 0 0 0 0 .7 .56 .56 0 0 0 .6 .2v1.5l-.3 .5-.7-.4-.9 .1-.2 1.2-.4-.4-.2-.8-.9-.1-.3 .3v.6l.3 .4h.6l.9 .9 2.4 .1 .4 .4 .2 1.2-.8 .2 .1 .8h2l.1-.8-.7-.1-.1-.3 .6-.2 .6 .4h1.1l.4-.7h-.8v.7h-.5v-1.2h1.3l-.1-.3-.7-.4v.7h-.5v-.7l-.8 .4-.9-.1-.7-.6-2.3-.1-.2-.2 1-.1 .4-.3 .6 .3h.6l.5-.3 .5 .6h1.1l.5-.7h-.8v.8h-.5v-1.3h1.3l-.1-.3-.7-.4v.7h-.5v-.7l-.9 .6-.3-.4v-1.8l.2-.3 .4 .6 2.1-.1 2.6 2.6-.9 .2-.3 .2v.8l.2 .3-.2 1.1v.7l.3 .2 1.1-.2 .7 .5h.8l.5-.4 .1-.3h-.8v.7h-.5v-1.2h1.3l-.5-.7-.3-.1v.8h-.5v-.8l-.8 .5-.6-.2 .1-.6 .4-.3v-1l.5 .3v.7l.3 .2h.7l.4-.3h2.3l.5 .5 .1 .6 .7 .3v3.9l.3 .5-.6 .8-1.7-1.7v-.6l-.2-.3h-1.9l-.4 .4-1-1-5.8-.1-.3 .3 .3 .6 5.6-.1 1.4 1.3v.7l-3.2 .1-1.6 1.5-.4-.6-1.8-.1 .2-.2 1.7-.1v-.8l-1.9-.1-1.5 1.8a.51 .51 0 0 0-.5 .7 .51 .51 0 0 0 .8 .2l-.1 .6-.6 .1-.6 .5-.5-.4 .1-.7-.2-.2-3.4 .1-.1-.4 .9-1.1 .7 1h2v-.9h-1.6l-.2-.2 1.8-.2 .7-1v-.9h2l.1 .5 .2 .2 2.7-.2a.45 .45 0 0 0 .6 0 .45 .45 0 0 0 0-.7 .45 .45 0 0 0-.7 .1l-2.6-.2-.3 .3h-2v-2.9l-.9-1a.45 .45 0 0 0-.5-.4 .45 .45 0 0 0-.4 .5 .45 .45 0 0 0 .5 .4l.4 .6-2.2 .2v-7.3l-.4-.5z"/>
<path d="M235.2 78.9l.4 .6h1.8l.5-.7 .1 .7 .4 .3h.6l.4-.3 5.2 .1a.49 .49 0 0 0-.3 .5 .49 .49 0 0 0 .5 .4l3.4 3.4-.1 3-2.3-2.2-.7-.1 .1-.2 .7-.2v-.6l-.2-.2h-1.1l-.1-.4a.46 .46 0 0 0 0-.7 .46 .46 0 0 0-.6 0 .46 .46 0 0 0 0 .7l-.3 1.1 .9 .4-.8 .3v.7l2.1 .1 1.9 1.9v4.4l1 .9h.8a.51 .51 0 0 0 .7-.1 .51 .51 0 0 0-.1-.7l.7-.1 .1-.6-.2-.3h-.6v-.2l.9-.3 2.6 2.5 3.7 .1 .7 .5-6 .1-1.5 .7-.4-.4-.4-.2-.2 1.5-.3-.1-.1-1.4-.7 .5-1.3-.1-.1-6.6-1-1.1-.2-.5-1.9-.1-.3 .3 .1 .7-.4 .5h1.4l.1 .5h-1.5l.4 .6-.2 .5-1.2-1.2-.1-6-.6-.7a.6 .6 0 0 0-.7-.2 .6 .6 0 0 0-.3 .7l.7 .1 .3 .2v1.1l-.8-.1-.5-.4h-1.7l.7-1.1-.2-1-1 .1 .1 1.2-1.1 .1-.2-.9 .7-.2v-.7l-2-.2a.5 .5 0 0 1-.7-.4z"/>
<path d="M248.8 86.9l2.1-.2h6.3l-.2 .7h1l.3 .4v.9l.5-.2 .3-.5 .4 .3h.6l.5-.3h4.3l.9 .9a1.72 1.72 0 0 0 .5 1.8l-5.7 .1-.2-1.2-1.3 .1-.8-.5 .1 2.1-1.1 1.1-3.4 .1-1.7-1.9 4.8-.1 .3 .5 .5 .2v-.7h-5.4l.4-.6 5 .1v-.8l-.5 .2-.3 .5-5.1-.1v-.5h.9l-.4-.8 .1-.3 .9-.2h3.6l.3 .5 .5 .2v-.8l-4.4 .1a.51 .51 0 0 0-.2-.7 .51 .51 0 0 0-.7 .2l-.4-.4h-.6l-.5 .4-.3-.3h-1.8z"/>
<path d="M200.7 89l.7-.6 .4 .3-.6 .6 .3 .3-.3 .2 .6 .6-.4 .4-.8-.7z"/>
<path d="M273.6 87.5l.7-.6 .4 .3-.6 .6 .3 .3-.3 .2 .6 .6-.4 .4-.8-.7z"/>
<path d="M275.2 87.2l.4-.3 .6 .5h.3v1.4l-.3-.1-.6 .6-.4-.4 .6-.6-.3-.2 .3-.3z"/>
<path d="M222.6 69.7l52.6-.1a1.27 1.27 0 0 1 1.3 1.3v14.8h-.3l-.6 .6-.4-.4 .5-.6a1.5 1.5 0 0 0-1.6 0l.6 .6-.4 .4-.6-.6-.3 1.7-.3-.4v-8.1l-2.5-2.5-1.8-.1v-3.4l-.2-.2h-2.4l-.4 .2-.6-.2-.1 1.2-.3 .3h-1l.1 .7-.4 .3-.4-.3h-3.8l-.3 .3-.4-.2h-6.4l-.2 .1-.1 7.5 .2 .3h16.5l.3-.3v-1.3h1a.79 .79 0 0 0 .8-1h-.8v1h-.5v-1.5h1.3a.79 .79 0 0 0-.8-1v1h-.5v-1h-.5v-1.6h1.3l2 2v6.6l-4.2 .2a1.21 1.21 0 0 0-1.8-.3 1.21 1.21 0 0 0 0 1.8 1.21 1.21 0 0 0 1.8-.2v1.6a1.59 1.59 0 0 0-1.7-.4l-1.2-1.1h-4.5l-.3-.4 .2-1.2-.3-.3-.9 .2-.1 .8 .4 .5-.5 .3-.5-.5 .1-1-.5-.4v-.5l.5-.3 .7 .5 1.2-.2 .3-.5h-.8v.7h-.5v-1.2h1.3l-.2-.5-.4-.3h-.2v.8h-.5v-.8l-.8 .5-1.3-.1-.1 .9 .2 1.1-.3 .6-8.5-.2 .1-.3 1.9-.1v-.7l-.8-.3 .8-.2 .1-.7-.2-.2h-1l-4.5-4.5-.8-.1 .2-.7-.2-.7 .6-.1 .4 .3a.91 .91 0 0 0 .7 1.3 .91 .91 0 0 0 1-1h.5l.2 .8 .6-.6 .4 .3-.7 .7 .6 .2 .8-.2-.7-.7 .4-.3 .6 .6 .2-.6-.2-.7-.6 .6-.4-.4 .7-.6-.6-.2-.8 .2 .7 .6-.4 .4-.6-.6-.2 .5h-.5a1.03 1.03 0 0 0-1.3-.7l-.5-.5h-2.4l-1.3 1.2-.8-.1a.54 .54 0 0 0 .3-.5 .54 .54 0 0 0-.5-.5l-1-1v-.4h-.9v-.5h.9v-.6h5.2l1-1h.4a.9 .9 0 0 0 .9-1h.5l.2 .8 .6-.6 .4 .3-.7 .7 .6 .2 .7-.3h14.4v.3h.8v-1l-.5 .2-.3 .5h-14.4l-.6-.6 .4-.3 .6 .6 .2-.9-.2-.4-.6 .6-.4-.4 .7-.6-.6-.2-.8 .2 .7 .6-.4 .4-.6-.6-.2 .5h-.5a.93 .93 0 0 0-1.1-.7 .93 .93 0 0 0-.6 1.3l-.8 .8h-6.9l-2-.3 .1-.2 1.8-.1v-.7h5.2v.1a.9 .9 0 0 0 1.4 .7 .9 .9 0 0 0 0-1.5 .9 .9 0 0 0-1.4 .7l-7.1-.2-.4 .6a.75 .75 0 0 1-1.3 .2h-1.2l-.2-.7-1.7-.1-.5-.5a.51 .51 0 0 0-.7-.1 .51 .51 0 0 0-.2 .7l-2.7 .1-.4-.2-.6 .5-1.3-1.4-.2-1-1.1 .1z"/>
<path d="M268.1 86.9h.5l.6 .5-.4 .4-.8-.7z"/>
<path d="M212.4 81l.2-.2 1.1-.1 .3-.5 .7 .7h3.1l.4 .3a.7 .7 0 0 0 0 1.2v.9l1.8 .2-1.8 .2v.8l2 .1a.71 .71 0 0 1 .7 .9h-.2l-.5-.6h-1.8l-.3 .3 .1 .6 1.9 .1 .2 .2-1.9 .1-.4 .3-1.8-1.4-.1-.5-.6-.5-.2-.4-1.7-.1 .1-.3h1.6v-.9h-1.1l-.6-.6h-1.3z"/>
<path d="M227.6 83.5l.4 .3h1.8l.3-.3-.2-.6h-1.4l-.1-.2 .3-.3h3l.1 .2-.5 .3-.2 .5h1v.3l-1 .2 .1 .4-1 .2-.4-.3h-1.8l-.3 .8h-1.4z"/>
<path d="M217.4 76.9l2-.1 .3 .3v.9l.8-.5 1 .2 .7-.4 .3 .9 1.8 .1 1.8-1.6 1.3 1.5 1.9 .1 .3-.3-.1-.7 .4-.5h-1.4l-.1-.4 1.5-.2-.3-.7 .9 .1-.4 .6h3a.47 .47 0 0 0 .4-.5 .47 .47 0 0 0-.5-.4l-.6-.5-2.8 .1-2.1-.3 .2-.2h1.6l1-.7 .4 .7 3.7-.1 .9 .8-2.2 2.4-.4-.2 .4-.5h-3l.4 .5-.1 .7 .3 .2 2.7-.1 1.8-1.8 .4 .7 2.3-.2 .2 .7 1 .2-1.3 .2-.4-.6h-1.8l-1.2 1.7a.53 .53 0 0 0-.6-.4 .53 .53 0 0 0-.5 .5l-.7 .8-1.9-.1-.5 .9-.6 .1-.2-.9-1.9-.1-.1-.2 2.2-.3 2.9 .2 .2-.2v-.6l-5.2-.1-1.1 .8h-1.7l-.1-.6-.3-.2-6.2 .1-.4-.6 .7-.6 .8 .5v-.7l-1.7 .1z"/>
<path d="M213.8 77.6l3.4-3.4h1l-.1-.9 1.1-.9 .1 1.1h-.6l-.1 .9-.3 .3h-.9l.2 .7-.6 .1-1 .9-.6 .1-.3 .2 .2 1h1.1l.6 .4-.3 .6-.6-.4h-.7l-.4 .7-1.2-1z"/>
</g>
</svg>
